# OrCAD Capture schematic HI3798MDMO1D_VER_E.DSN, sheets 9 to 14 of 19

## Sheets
9 SHEET09: size Custom
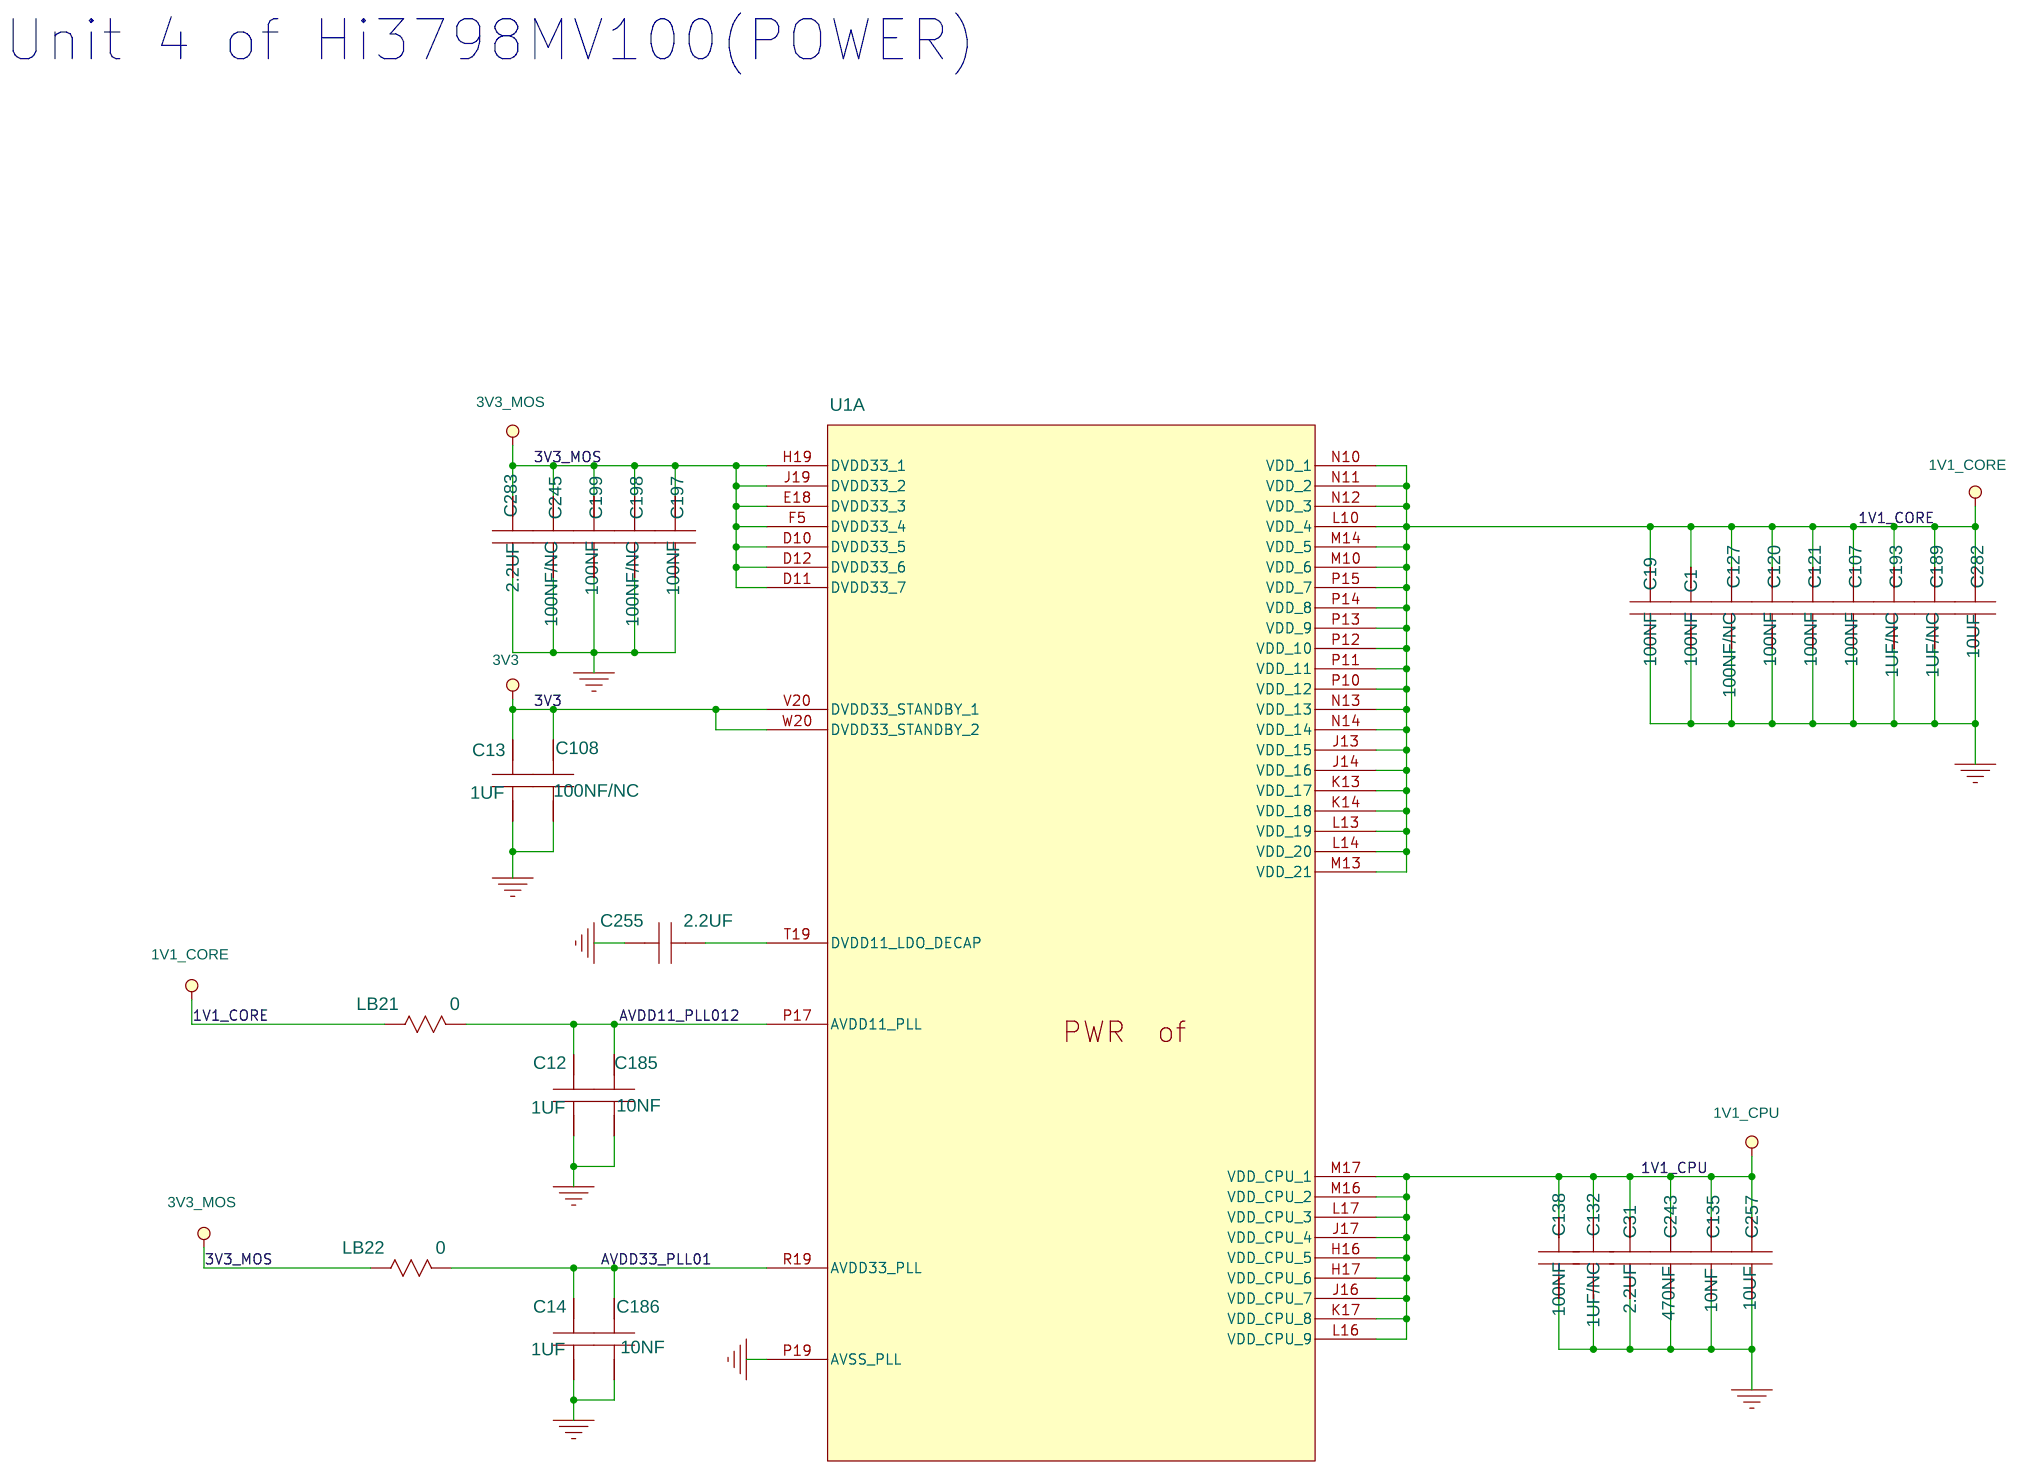
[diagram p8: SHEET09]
10 SHEET10: size Custom
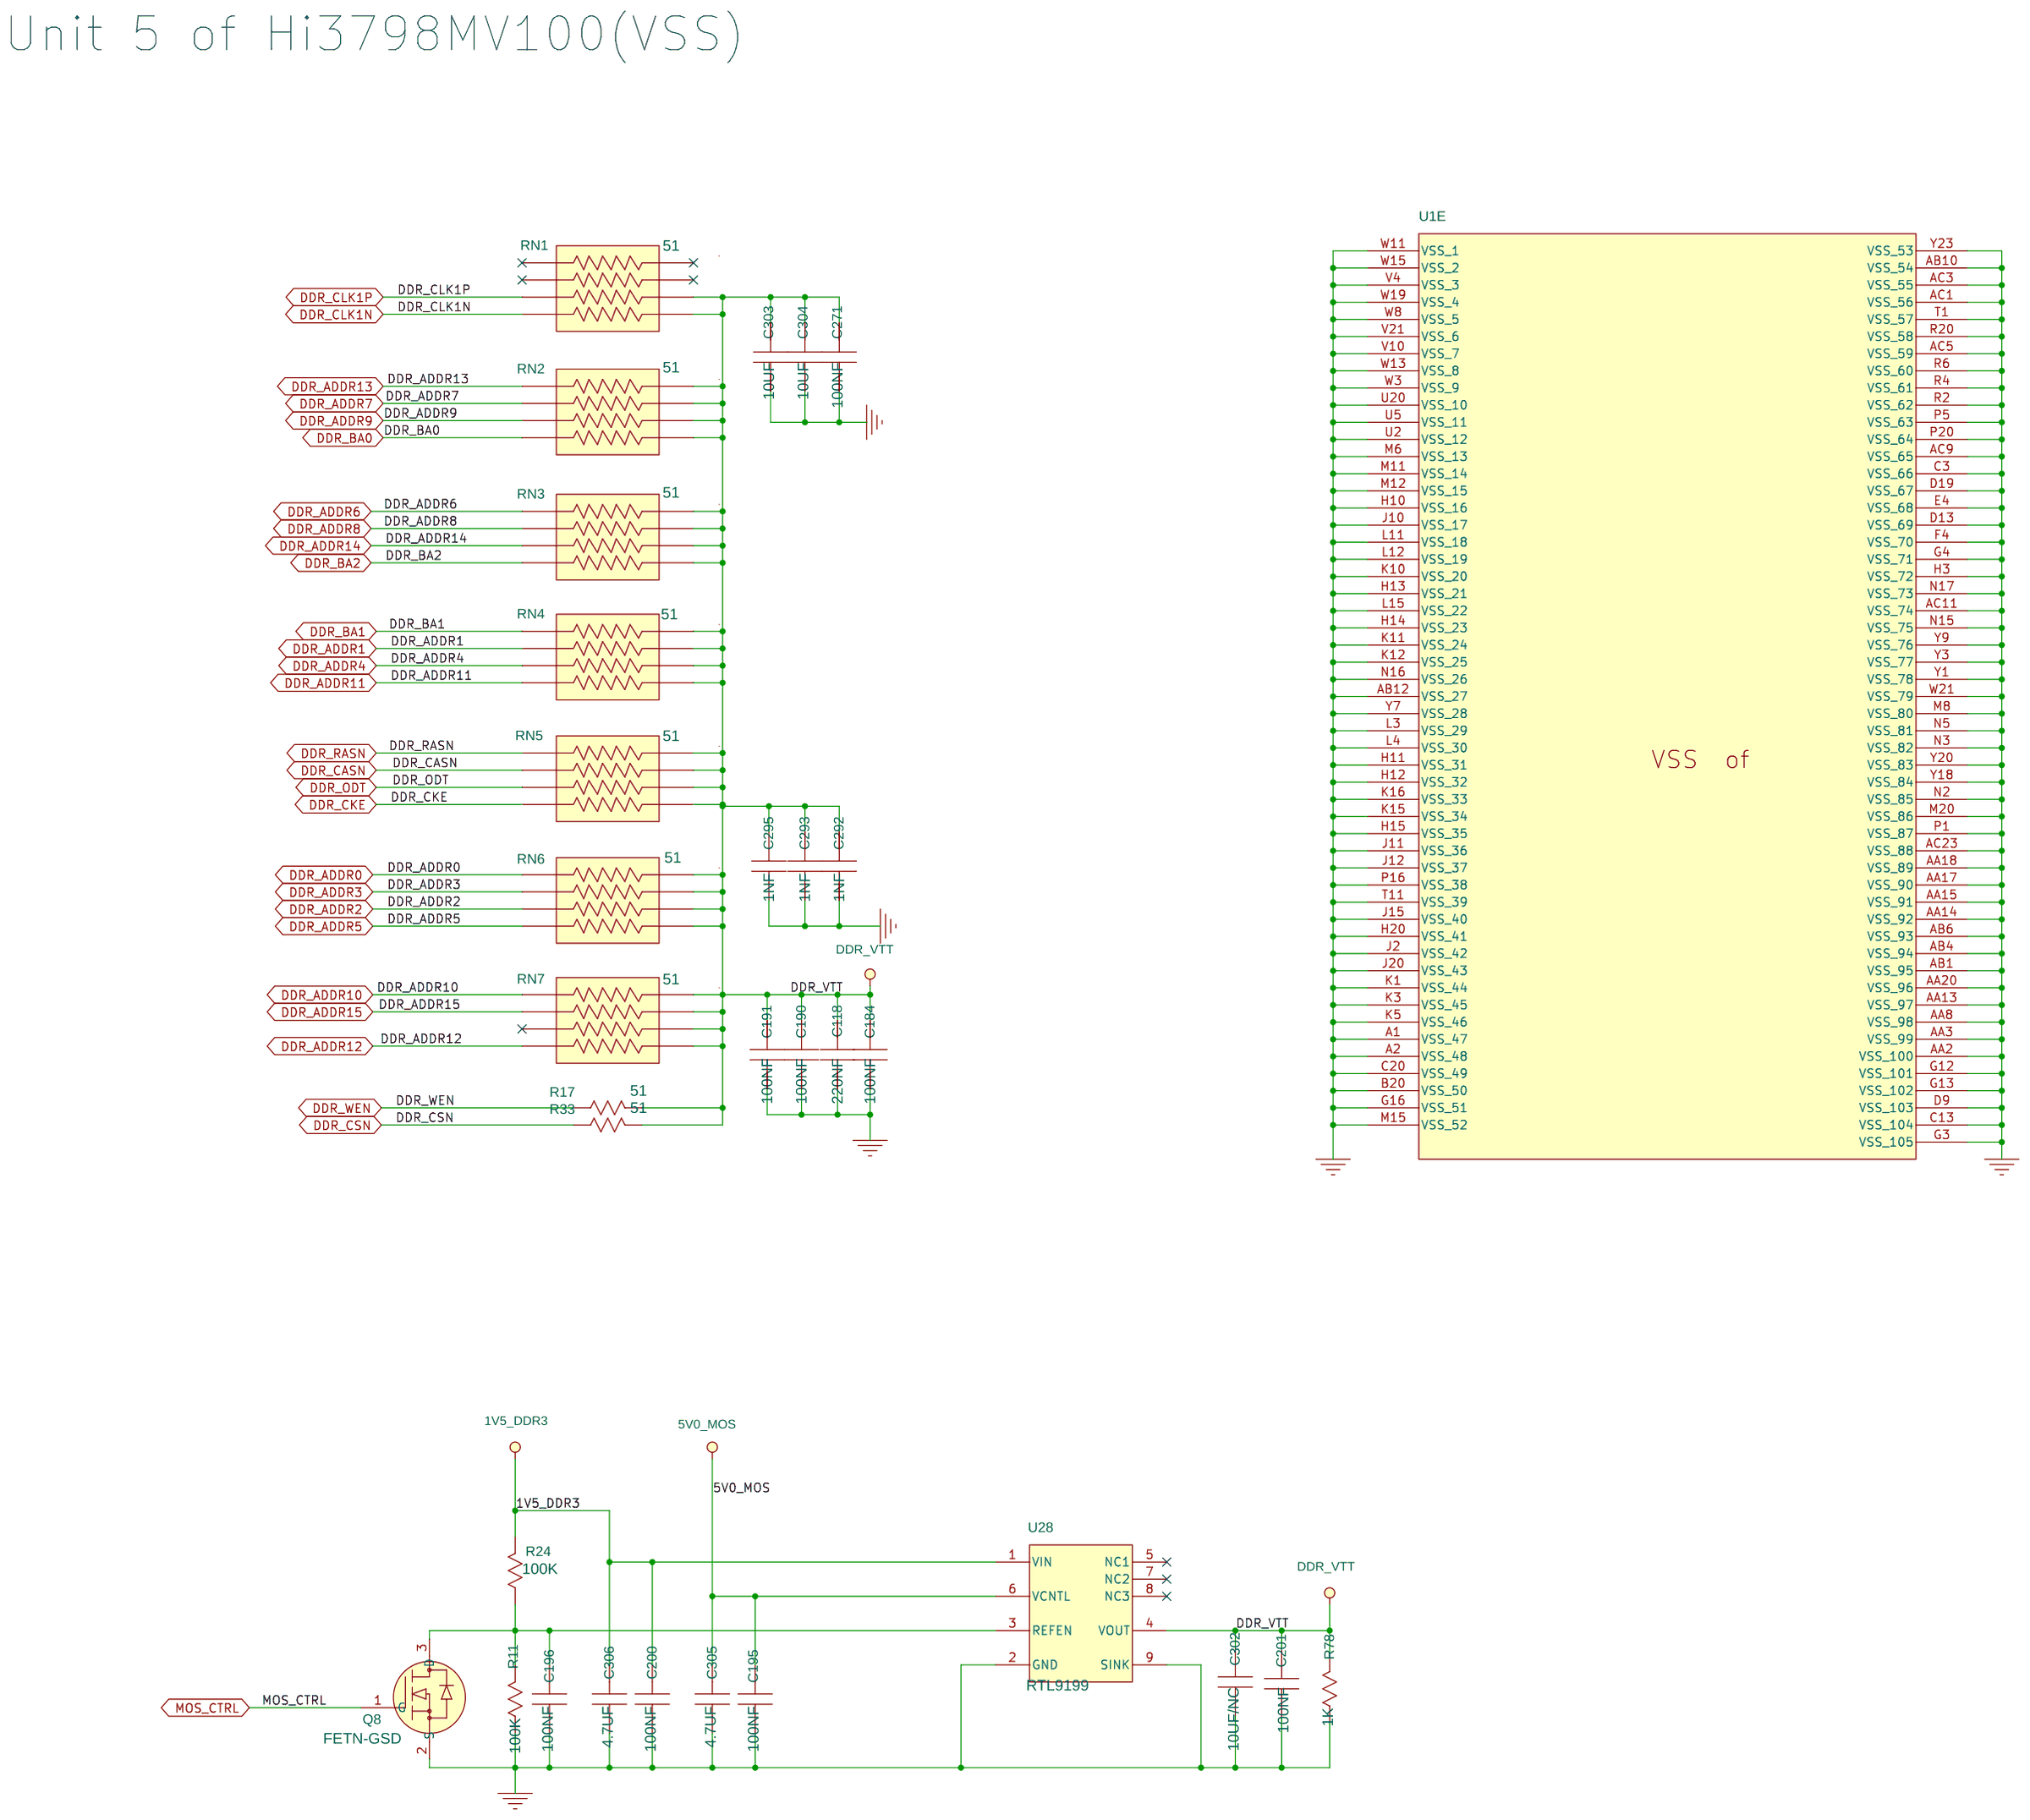
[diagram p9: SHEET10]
11 SHEET11: size Custom
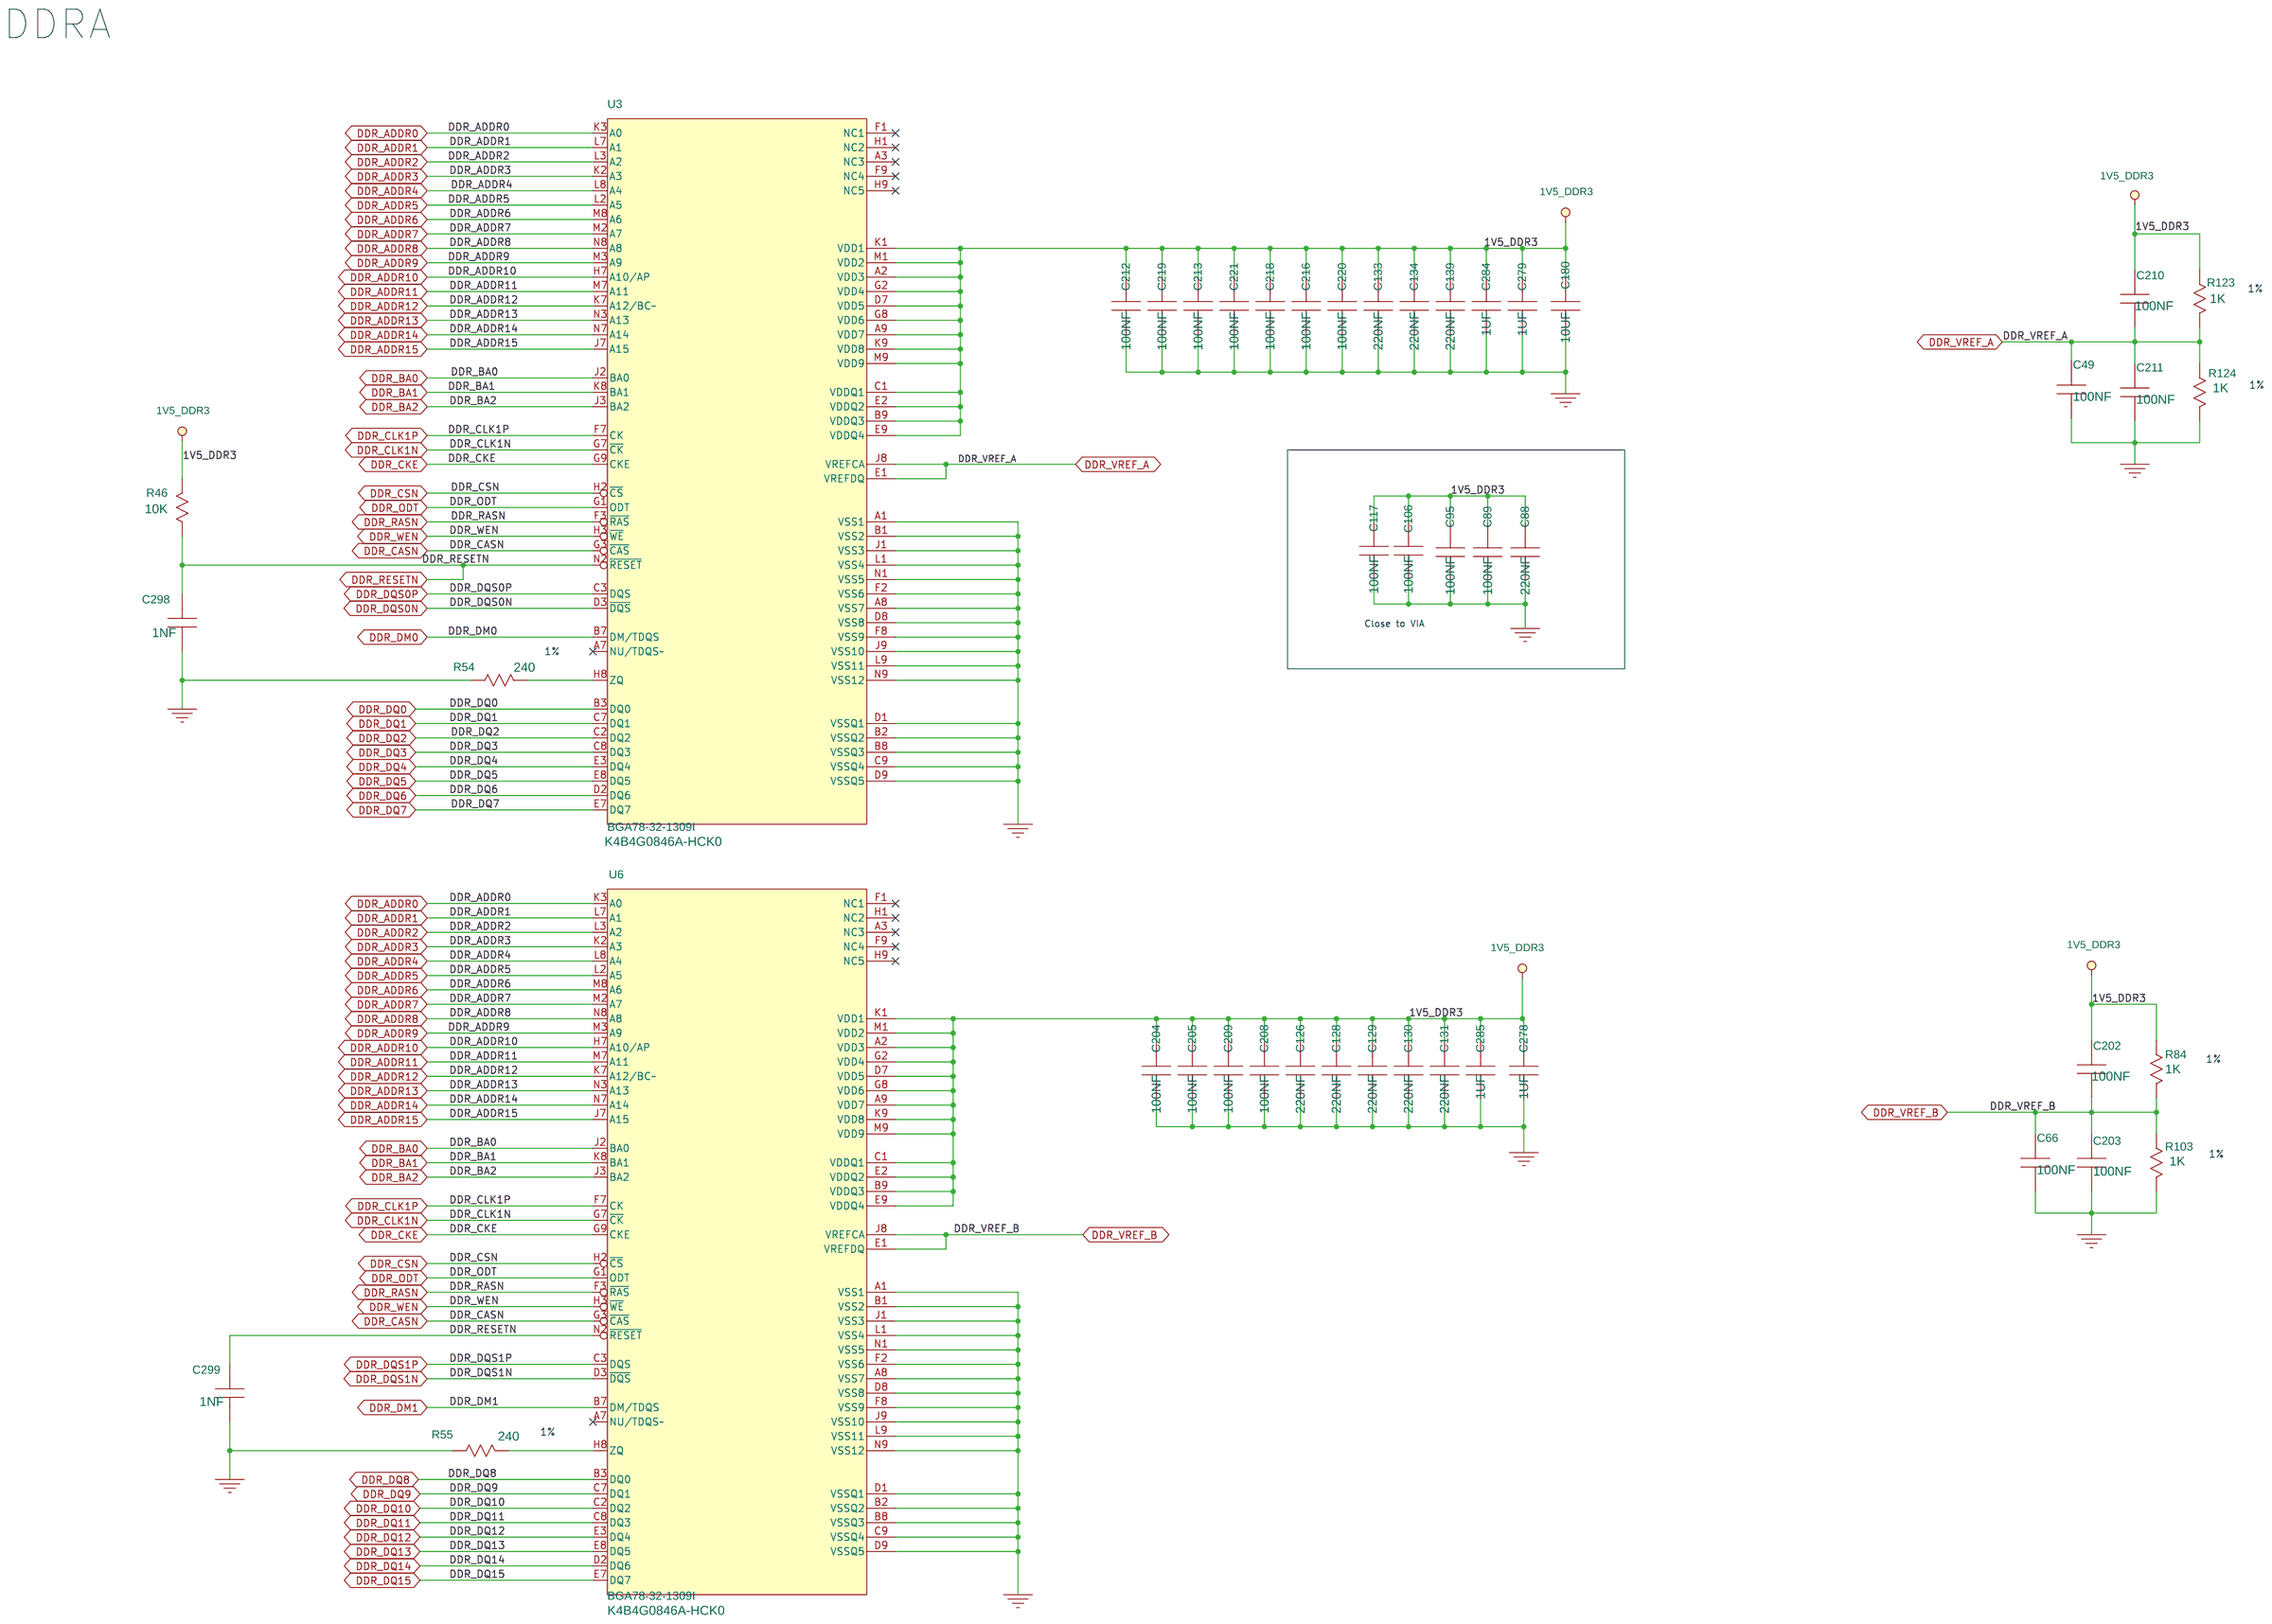
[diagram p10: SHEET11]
12 SHEET12: size Custom
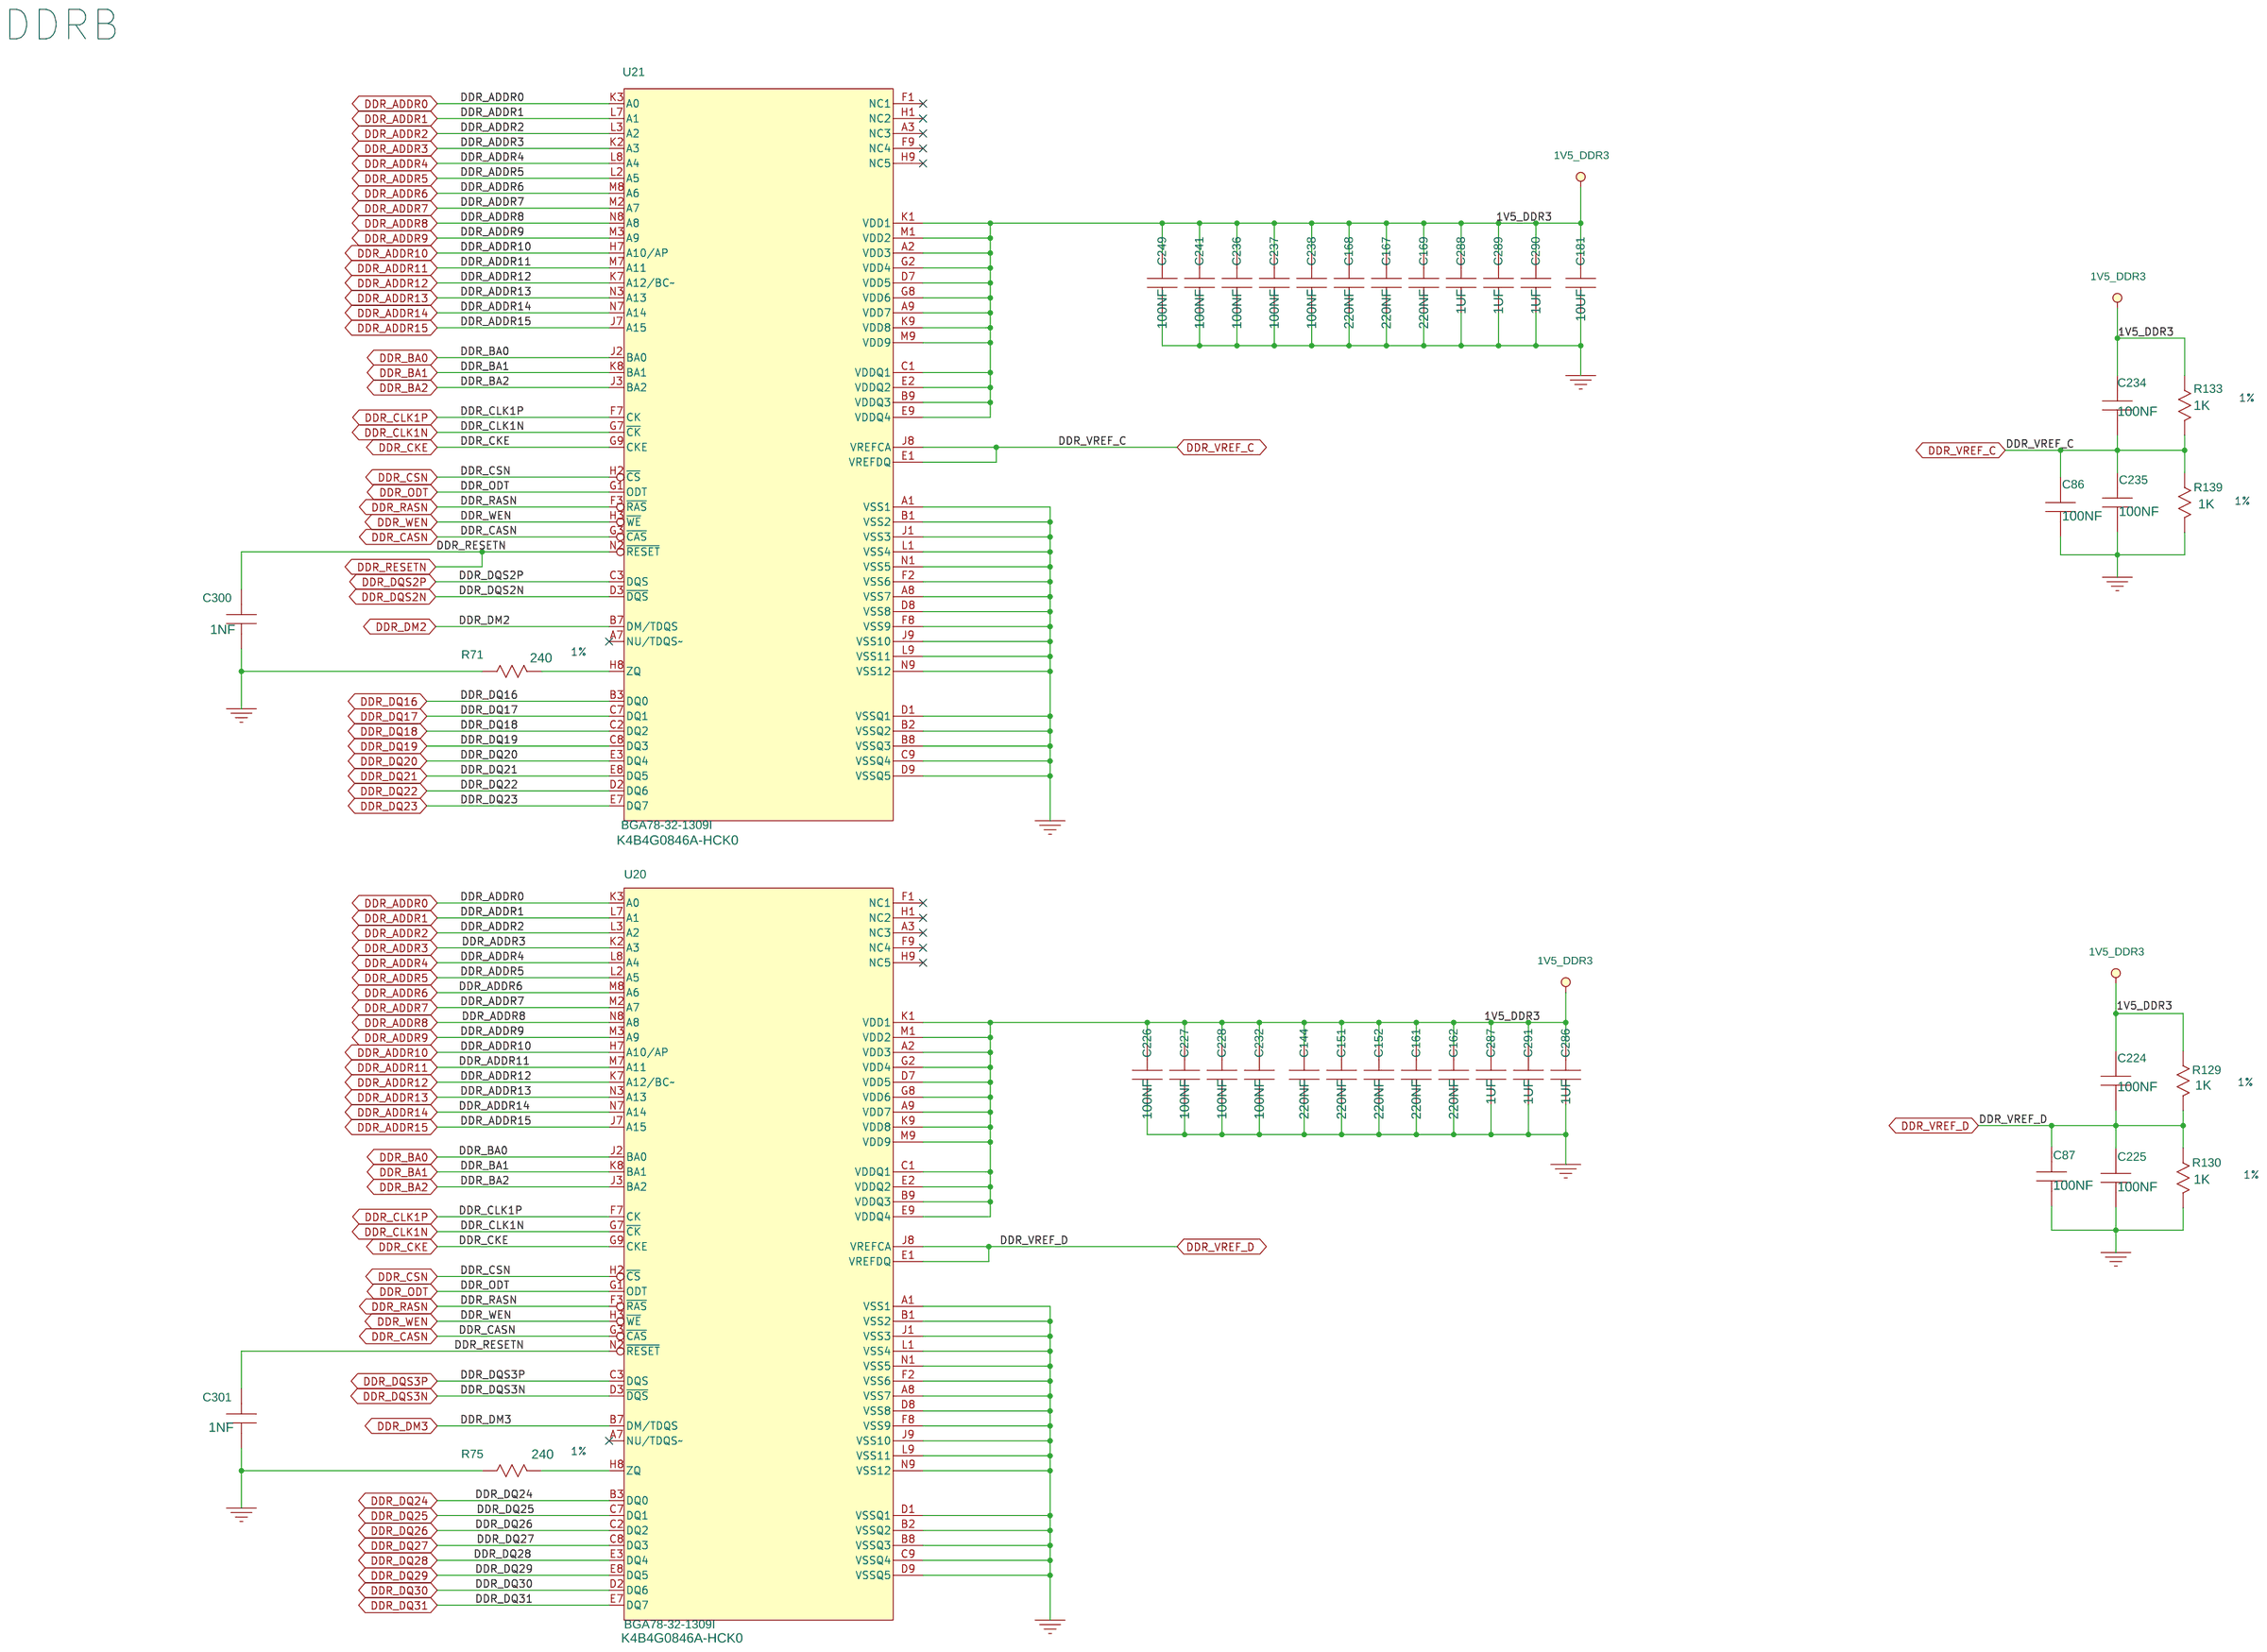
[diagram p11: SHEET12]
13 SHEET13: size Custom
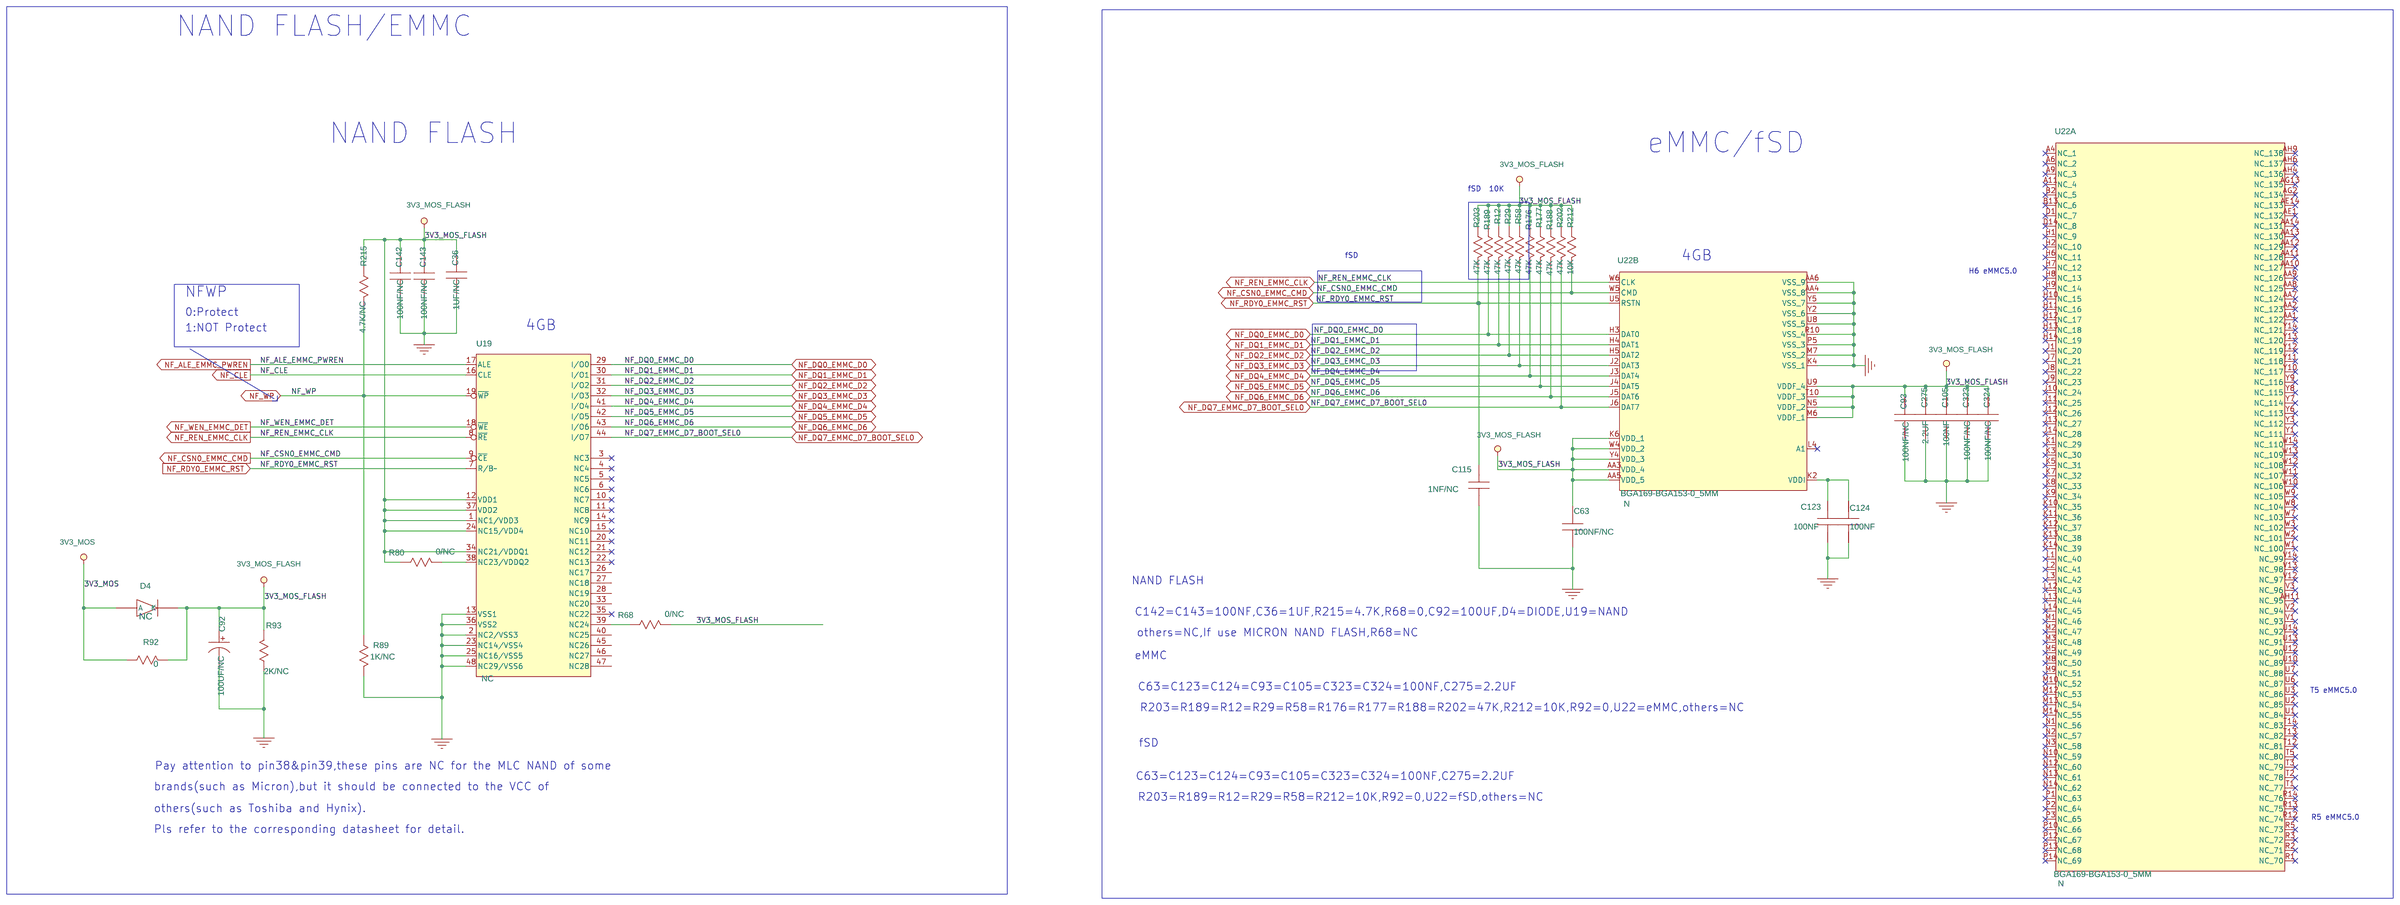
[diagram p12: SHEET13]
14 SHEET14: size Custom

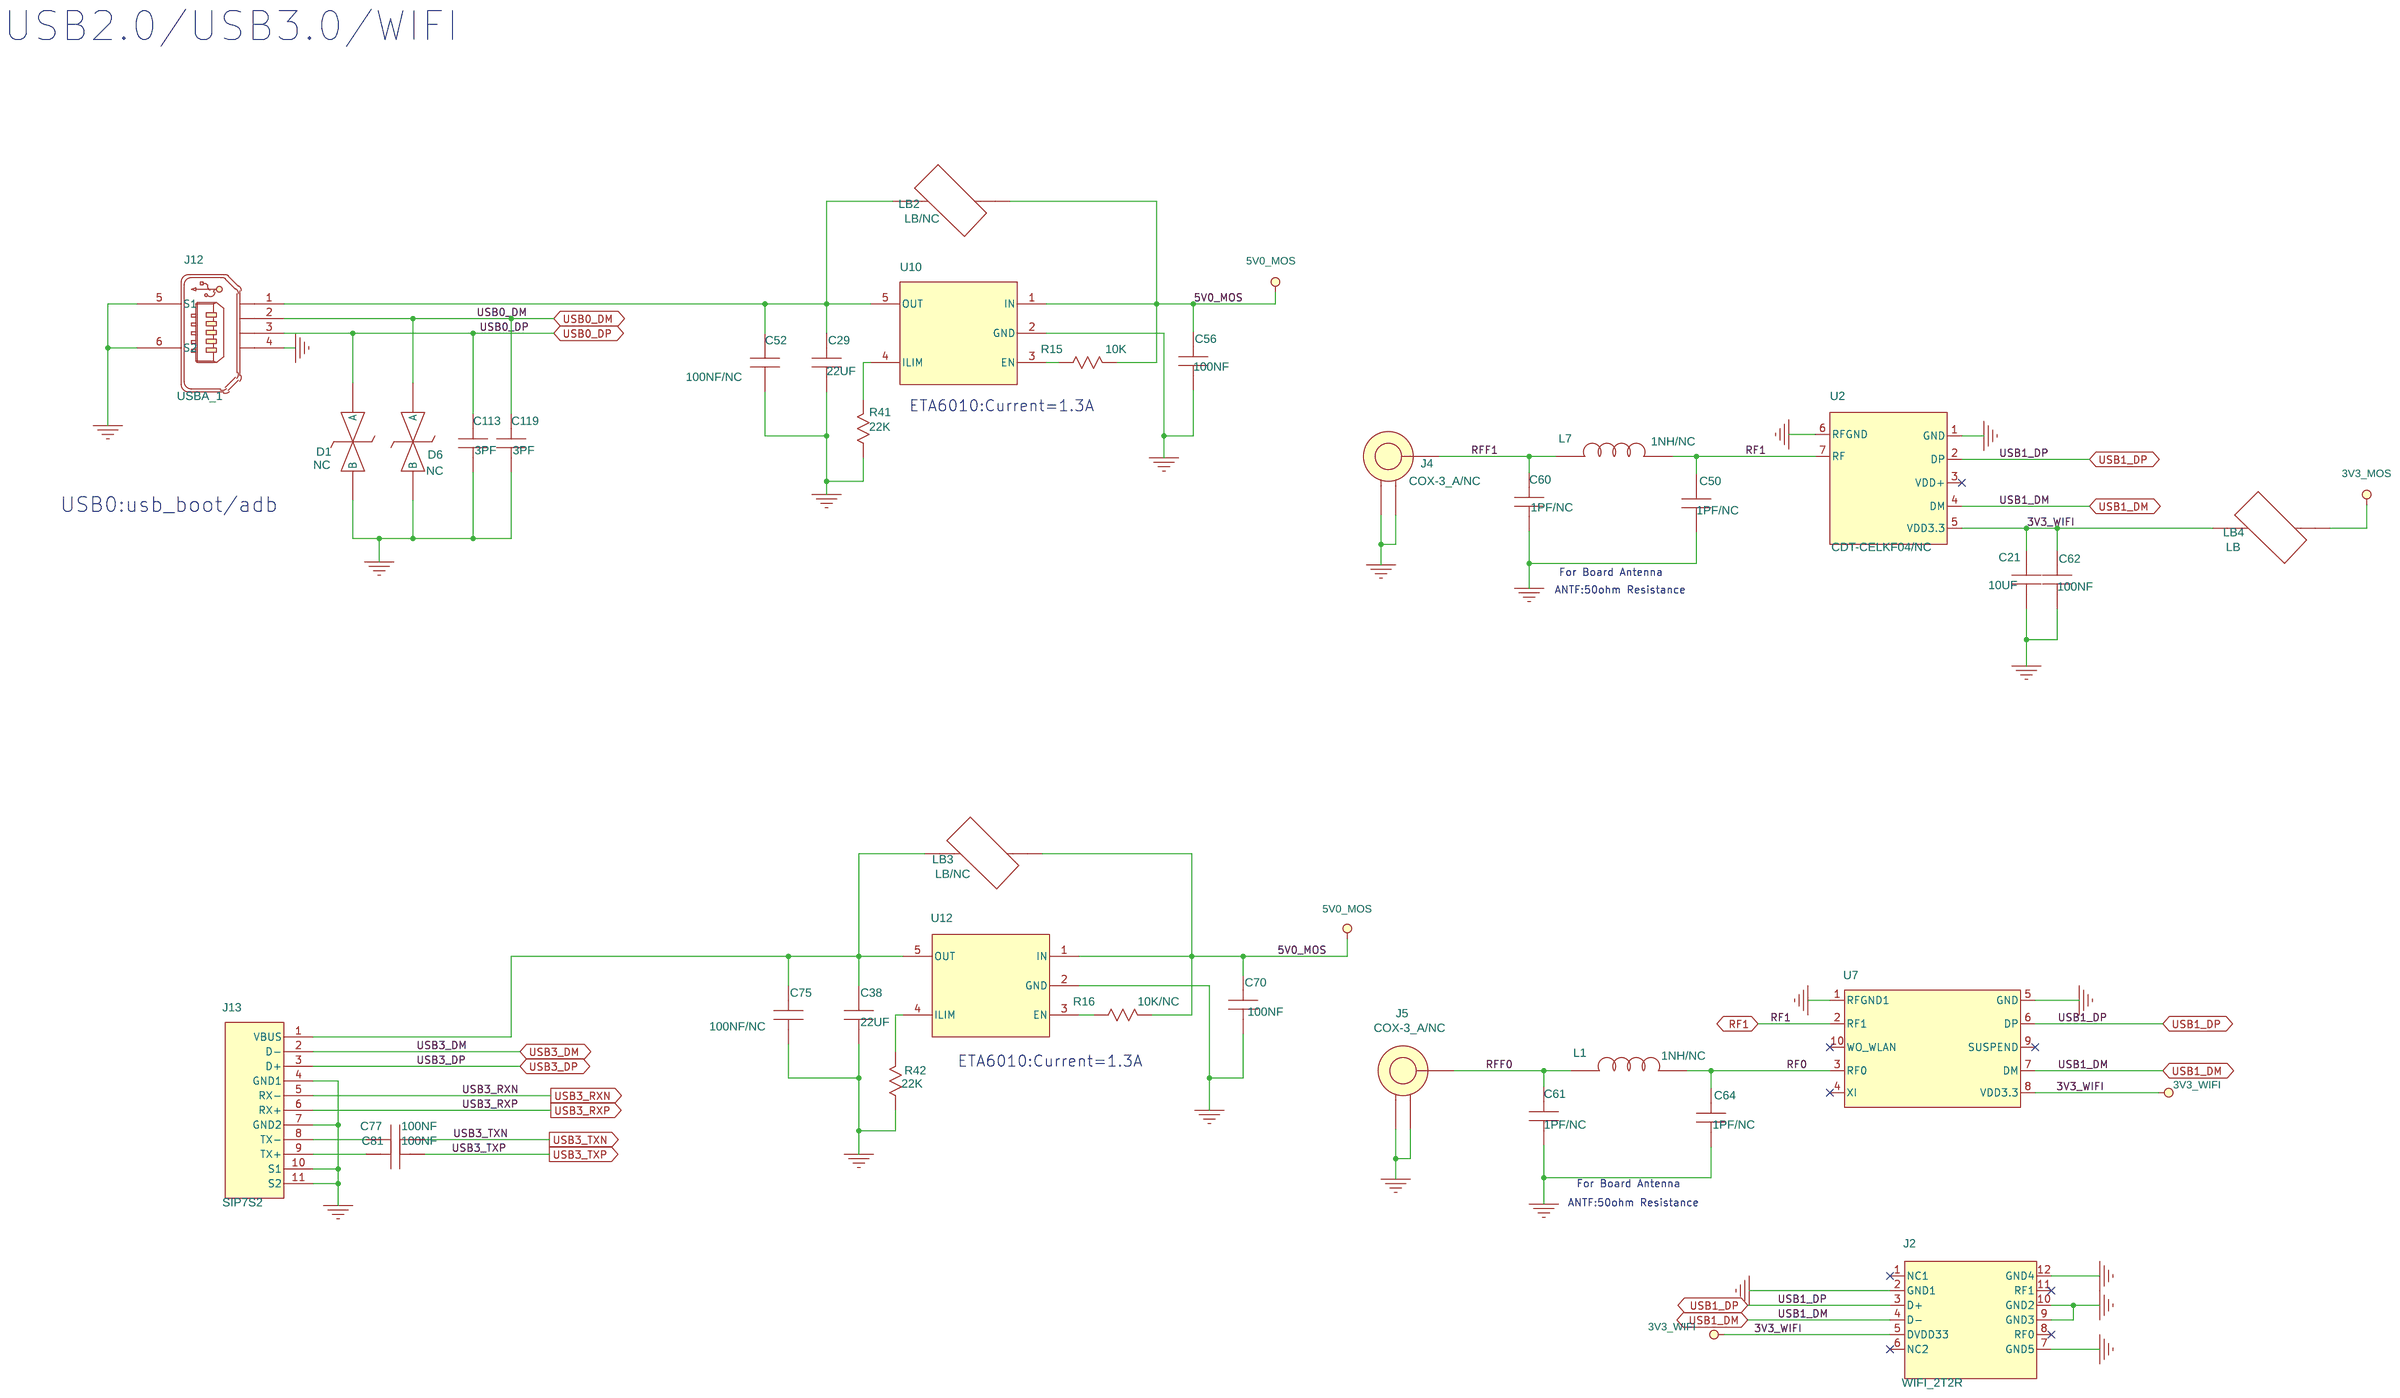
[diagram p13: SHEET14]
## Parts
sheet SHEET07
U1  Hi3798MV100_A  [TFBGA395-32-2323]  (sections A,B,C,D,E)
sheet SHEET09
C1  100NF  [SC0402]
C12  1UF  [SC0402]
C13  1UF  [SC0603]
C14  1UF  [SC0402]
C19  100NF  [SC0402]
C31  2.2UF  [HSC0402]
C107  100NF  [SC0402]
C108  100NF/NC  [SC0402]
C120  100NF  [SC0402]
C121  100NF  [SC0402]
C127  100NF/NC  [SC0402]
C132  1UF/NC  [SC0402]
C135  10NF  [HSC0402]
C138  100NF  [SC0402]
C185  10NF  [SC0402]
C186  10NF  [SC0402]
C189  1UF/NC  [SC0402]
C193  1UF/NC  [SC0402]
C197  100NF  [SC0402]
C198  100NF/NC  [SC0402]
C199  100NF  [SC0402]
C243  470NF  [SC0402]
C245  100NF/NC  [SC0402]
C255  2.2UF  [HSC0402]
C257  10UF  [SC0603]
C282  10UF  [SC0603]
C283  2.2UF  [SC0603]
LB21  0  [SL0603]
LB22  0  [SL0603]
sheet SHEET10
C118  220NF  [SC0402]
C184  100NF  [SC0402]
C190  100NF  [SC0402]
C191  100NF  [SC0402]
C195  100NF  [SC0402]
C196  100NF  [SC0402]
C200  100NF  [SC0402]
C201  100NF  [SC0402]
C271  100NF  [SC0402]
C292  1NF  [SC0402]
C293  1NF  [SC0402]
C295  1NF  [SC0402]
C302  10UF/NC  [SC0603]
C303  10UF  [SC0603]
C304  10UF  [SC0603]
C305  4.7UF  [SC0603]
C306  4.7UF  [SC0603]
Q8  FETN-GSD  [HSOT-SC70]
R11  100K  [SR0402]
R17  51  [SR0402]
R24  100K  [SR0402]
R33  51  [SR0402]
R78  1K  [SR0402]
RN1  51  [SRN8-0804]
RN2  51  [SRN8-0804]
RN3  51  [SRN8-0804]
RN4  51  [SRN8-0804]
RN5  51  [SRN8-0804]
RN6  51  [SRN8-0804]
RN7  51  [SRN8-0804]
U28  RTL9199  [SOP8H-50-200]
sheet SHEET11
C49  100NF  [SC0402]
C66  100NF  [SC0402]
C88  220NF  [SC0402]
C89  100NF  [SC0402]
C95  100NF  [SC0402]
C106  100NF  [SC0402]
C117  100NF  [SC0402]
C126  220NF  [SC0402]
C128  220NF  [SC0402]
C129  220NF  [SC0402]
C130  220NF  [SC0402]
C131  220NF  [SC0402]
C133  220NF  [SC0402]
C134  220NF  [SC0402]
C139  220NF  [SC0402]
C180  10UF  [SC0603]
C202  100NF  [SC0402]
C203  100NF  [SC0402]
C204  100NF  [SC0402]
C205  100NF  [SC0402]
C208  100NF  [SC0402]
C209  100NF  [SC0402]
C210  100NF  [SC0402]
C211  100NF  [SC0402]
C212  100NF  [SC0402]
C213  100NF  [SC0402]
C216  100NF  [SC0402]
C218  100NF  [SC0402]
C219  100NF  [SC0402]
C220  100NF  [SC0402]
C221  100NF  [SC0402]
C278  1UF  [SC0402]
C279  1UF  [SC0402]
C284  1UF  [SC0402]
C285  1UF  [SC0402]
C298  1NF  [SC0402]
C299  1NF  [SC0402]
R46  10K  [SR0402]
R54  240  [SR0402]
R55  240  [SR0402]
R84  1K  [SR0402]
R103  1K  [SR0402]
R123  1K  [SR0402]
R124  1K  [SR0402]
U3  K4B4G0846A-HCK0  [BGA78-32-1309I]
U6  K4B4G0846A-HCK0  [BGA78-32-1309I]
sheet SHEET12
C86  100NF  [SC0402]
C87  100NF  [SC0402]
C144  220NF  [SC0402]
C151  220NF  [SC0402]
C152  220NF  [SC0402]
C161  220NF  [SC0402]
C162  220NF  [SC0402]
C167  220NF  [SC0402]
C168  220NF  [SC0402]
C169  220NF  [SC0402]
C181  10UF  [SC0603]
C224  100NF  [SC0402]
C225  100NF  [SC0402]
C226  100NF  [SC0402]
C227  100NF  [SC0402]
C228  100NF  [SC0402]
C232  100NF  [SC0402]
C234  100NF  [SC0402]
C235  100NF  [SC0402]
C236  100NF  [SC0402]
C237  100NF  [SC0402]
C238  100NF  [SC0402]
C241  100NF  [SC0402]
C249  100NF  [SC0402]
C286  1UF  [SC0402]
C287  1UF  [SC0402]
C288  1UF  [SC0402]
C289  1UF  [SC0402]
C290  1UF  [SC0402]
C291  1UF  [SC0402]
C300  1NF  [SC0402]
C301  1NF  [SC0402]
R71  240  [SR0402]
R75  240  [SR0402]
R129  1K  [SR0402]
R130  1K  [SR0402]
R133  1K  [SR0402]
R139  1K  [SR0402]
U20  K4B4G0846A-HCK0  [BGA78-32-1309I]
U21  K4B4G0846A-HCK0  [BGA78-32-1309I]
sheet SHEET13
C36  1UF/NC  [SC0603]
C63  100NF/NC  [SC0402]
C92  100UF/NC  [SAC6666]
C93  100NF/NC  [SC0402]
C105  100NF  [SC0402]
C115  1NF/NC  [SC0402]
C123  100NF  [SC0402]
C124  100NF  [SC0402]
C142  100NF/NC  [SC0402]
C143  100NF/NC  [SC0402]
C275  2.2UF  [SC0603]
C323  100NF/NC  [SC0402]
C324  100NF/NC  [SC0402]
D4  NC  [HSOD323A]
R12  47K  [SR0402]
R29  47K  [SR0402]
R58  47K  [SR0402]
R68  0/NC  [SR0402]
R80  0/NC  [SR0402]
R89  1K/NC  [SR0402]
R92  0  [SR1206]
R93  2K/NC  [SR0603]
R176  47K  [SR0402]
R177  47K  [SR0402]
R188  47K  [SR0402]
R189  47K  [SR0402]
R202  47K  [SR0402]
R203  47K  [SR0402]
R212  10K  [SR0402]
R215  4.7K/NC  [SR0402]
U19  NC  [SOP48-20-720B]
U22  N  [BGA169-BGA153-0_5MM]  (sections A,B)
sheet SHEET14
C21  10UF  [SC0603]
C29  22UF  [SC0805]
C38  22UF  [SC0805]
C50  1PF/NC  [SC0402]
C52  100NF/NC  [SC0603]
C56  100NF  [SC0603]
C60  1PF/NC  [SC0402]
C61  1PF/NC  [SC0402]
C62  100NF  [SC0603]
C64  1PF/NC  [SC0402]
C70  100NF  [SC0603]
C75  100NF/NC  [SC0603]
C77  100NF  [SC0402]
C81  100NF  [SC0402]
C113  3PF  [SC0402]
C119  3PF  [SC0402]
D1  NC  [SC0402]
D6  NC  [SC0402]
J2  WIFI_2T2R  [SIP12-2_0MM-1827]
J4  COX-3_A/NC  [HSCOX-AMC-TM-A]
J5  COX-3_A/NC  [HSCOX-AMC-TM-A]
J12  USBA_1  [USB4-1415]
J13  SIP7S2  [USB3_0_9P_DIP_MAINSUPER]
L1  1NH/NC  [SL0402]
L7  1NH/NC  [SL0402]
LB2  LB/NC  [SL0603]
LB3  LB/NC  [SL0603]
LB4  LB  [SL0805]
R15  10K  [SR0402]
R16  10K/NC  [SR0402]
R41  22K  [SR0402]
R42  22K  [SR0402]
U2  CDT-CELKF04/NC  [CDTWIFI]
U7  NC  [CDTWIFI10]
U10  NC  [SOT23-5]
U12  NC  [SOT23-5]

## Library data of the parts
U1 = Hi3798MV100: CaptureCellPackProp: S40V300_19X19_VSSA
C1 C19 C49 C66 C77 C81 C86 C87 C89 C93 C95 C105-C108 C115 C117 C120 C121 C123 C124 C127 C138 C197-C199 C202-C205 C208-C213 C216 C218-C221 C224-C228 C232 C234-C238 C241 C245 C249 C323 C324 = C: %182%%238%%182%%168%%185%%164%%215%%247%%181%%231%%209%%185%(V): 10; %195%%232%%202%%246%: SMD陶瓷电容-10V-100NF-+/-10%-X5R-0402; %208%%161%%192%%224%%195%%251%%179%%198%: SMD陶瓷电容; CODE: 8070561; COMPONENT_HIGH_MAX: 0.55MM; DEVICE: C0402C104K8PAC_7867
C12 C14 C132 C189 C193 C278 C279 C284-C291 = C: %182%%238%%182%%168%%185%%164%%215%%247%%181%%231%%209%%185%(V): 10; %195%%232%%202%%246%: SMD陶瓷电容-10V-1000NF-+/-10%-X5R-0402-BT,TS16949; %208%%161%%192%%224%%195%%251%%179%%198%: SMD陶瓷电容; CODE: 8070612; COMPONENT_HIGH_MAX: 0.55MM; DEVICE: CV05X5R105K10AH
C13 C36 = C: %182%%238%%182%%168%%185%%164%%215%%247%%181%%231%%209%%185%(V): 25; %195%%232%%202%%246%: SMD陶瓷电容-25V-1000NF-+/-10%-X7R-0603; %208%%161%%192%%224%%195%%251%%179%%198%: SMD陶瓷电容; CODE: 8070962; COMPONENT_HIGH_MAX: 0.9MM; DEVICE: CETMK107B7105KA_T
C31 C255 = C: %182%%238%%182%%168%%185%%164%%215%%247%%181%%231%%209%%185%(V): 6.3; %195%%232%%202%%246%: SMD陶瓷电容-6.3V-2200NF-+/-20%-X5R-0402-TS16949; %208%%161%%192%%224%%195%%251%%179%%198%: SMD陶瓷电容; CODE: 8070667; COMPONENT_HIGH_MAX: 0.6MM; DEVICE: GRM155R60J225ME15D
C135 C185 C186 = C: %182%%238%%182%%168%%185%%164%%215%%247%%181%%231%%209%%185%(V): 16; %195%%232%%202%%246%: SMD陶瓷电容-16V-10NF-+/-10%-X7R-0402-BT,TS16949; %208%%161%%192%%224%%195%%251%%179%%198%: SMD陶瓷电容; CODE: 8070449; COMPONENT_HIGH_MAX: 0.55MM; DEVICE: GRM155R71C103KA01D
C243 = C: %182%%238%%182%%168%%185%%164%%215%%247%%181%%231%%209%%185%(V): 6.3; %195%%232%%202%%246%: SMD陶瓷电容-6.3V-470NF-+/-10%-X5R-0402; %208%%161%%192%%224%%195%%251%%179%%198%: SMD陶瓷电容; CODE: 8070625; COMPONENT_HIGH_MAX: 0.55MM; DEVICE: GRM155R60J474KE19D
C21 C257 C282 C302-C304 = C: %182%%238%%182%%168%%185%%164%%215%%247%%181%%231%%209%%185%(V): 6.3; %195%%232%%202%%246%: SMD陶瓷电容-6.3V-10000NF-+/-20%-X5R-0603-BT,TS16949; %208%%161%%192%%224%%195%%251%%179%%198%: SMD陶瓷电容; CODE: 8070649; COMPONENT_HIGH_MAX: 0.9MM; DEVICE: C1608X5R0J106MT0A0E
C283 = C: %182%%238%%182%%168%%185%%164%%215%%247%%181%%231%%209%%185%(V): 6.3; %195%%232%%202%%246%: SMD陶瓷电容-6.3V-2200NF-+/-10%-X5R-0603-BT; %208%%161%%192%%224%%195%%251%%179%%198%: SMD陶瓷电容; CODE: 8070563; COMPONENT_HIGH_MAX: 0.95MM; DEVICE: CM105X5R225K06AT
LB21 LB22 R68 R80 = R: %182%%238%%182%%168%%185%%166%%194%%202%(W): 0.06; %195%%232%%202%%246%: 片式厚膜电阻器-0.0625W-0OHM-< 50MOHM-0402-1A-BT; %208%%161%%192%%224%%195%%251%%179%%198%: 片式厚膜电阻器; %215%%232%%214%%181%%212%%202%%208%%237%%198%%171%%178%%238%: < 50MOHM; CODE: 7090800; COMPONENT_HIGH_MAX: 0.4MM; DEVICE: RC0402JR_070R
C88 C118 C126 C128-C131 C133 C134 C139 C144 C151 C152 C161 C162 C167-C169 = C: %182%%238%%182%%168%%185%%164%%215%%247%%181%%231%%209%%185%(V): 6.3; %195%%232%%202%%246%: SMD陶瓷电容-6.3V-220NF-+/-10%-X5R-0402-BT; %208%%161%%192%%224%%195%%251%%179%%198%: SMD陶瓷电容; CODE: 8070584; COMPONENT_HIGH_MAX: 0.55MM; DEVICE: GRM155R60J224KE01D
C184 C190 C191 C195 C196 C200 C201 C271 = C: %182%%238%%182%%168%%185%%164%%215%%247%%181%%231%%209%%185%(V): 16; %195%%232%%202%%246%: SMD陶瓷电容-16V-100NF-+/-10%-X7R-0402-BT; %208%%161%%192%%224%%195%%251%%179%%198%: SMD陶瓷电容; CODE: 8070614; COMPONENT_HIGH_MAX: 0.6MM; DEVICE: RMEMK105BJ104KV_FR
C63 C292 C293 C295 C298-C301 = C: %182%%238%%182%%168%%185%%164%%215%%247%%181%%231%%209%%185%(V): 50; %195%%232%%202%%246%: SMD陶瓷电容-50V-1NF-+/-10%-X7R-0402-BT; %208%%161%%192%%224%%195%%251%%179%%198%: SMD陶瓷电容; CODE: 8070531; COMPONENT_HIGH_MAX: 0.56MM; DEVICE: 04025C102KAT2A
C305 C306 = C: %182%%238%%182%%168%%185%%164%%215%%247%%181%%231%%209%%185%(V): 6.3; %195%%232%%202%%246%: SMD陶瓷电容-6.3V-4700NF-+/-20%-X5R-0603-BT,TS16949; %208%%161%%192%%224%%195%%251%%179%%198%: SMD陶瓷电容; CODE: 8070564; COMPONENT_HIGH_MAX: 0.95MM; DEVICE: CM105X5R475M06AT
Q8 = FETN-GSD: %195%%232%%202%%246%: MOSFET-N沟道-60V-0.3A-2000MOHM-20V-SOT323-供电专用; %208%%161%%192%%224%%195%%251%%179%%198%: MOSFET; CODE: 15060225; COMPONENT_HIGH_MAX: 1.1MM; DEVICE: 2N7002WT1G
R11 R24 = R: %182%%238%%182%%168%%185%%166%%194%%202%(W): 0.06; %195%%232%%202%%246%: 片式厚膜电阻器-0.0625W-100000OHM-+/-5%-0402-BT; %208%%161%%192%%224%%195%%251%%179%%198%: 片式厚膜电阻器; %215%%232%%214%%181%%212%%202%%208%%237%%198%%171%%178%%238%: +/-5%; CODE: 7090831; DEVICE: RK73B1ELTP104J
R17 R33 = R: %182%%238%%182%%168%%185%%166%%194%%202%(W): 0.06; %195%%232%%202%%246%: 片式厚膜电阻器-0.0625W-51OHM-+/-5%-0402; %208%%161%%192%%224%%195%%251%%179%%198%: 片式厚膜电阻器; %215%%232%%214%%181%%212%%202%%208%%237%%198%%171%%178%%238%: +/-5%; CODE: 7090610; COMPONENT_HIGH_MAX: 0.4MM; DEVICE: RC0402JR_0751R
R78 R84 R103 R123 R124 R129 R130 R133 R139 = R: %182%%238%%182%%168%%185%%166%%194%%202%(W): 0.06; %195%%232%%202%%246%: 片式厚膜电阻器-0.0625W-1000OHM-+/-1%-0402-BT; %208%%161%%192%%224%%195%%251%%179%%198%: 片式厚膜电阻器; %215%%232%%214%%181%%212%%202%%208%%237%%198%%171%%178%%238%: +/-1%; CODE: 7091282; COMPONENT_HIGH_MAX: 0.4MM; DEVICE: RC0402FR_071KL
RN1-RN7 = RND8-4: %195%%232%%202%%246%: 电阻网络-0.0625W-51OHM-4个-8PIN-+/-5%-SMT-小型-独立式-2.0*1.0*0.45-0.5MM; %208%%161%%192%%224%%195%%251%%179%%198%: 电阻网络; %215%%232%%214%%181%%212%%202%%208%%237%%198%%171%%178%%238%: +/-5%; CODE: 7080125; COMPONENT_HIGH_MAX: 0.5MM; DEVICE: CN1E4KTTD510J
U28 = RTL9199
C180 C181 = C: %182%%238%%182%%168%%185%%164%%215%%247%%181%%231%%209%%185%(V): 25; %195%%232%%202%%246%: SMD陶瓷电容-25V-10000NF-+80%-20%-Y5V-1206; %208%%161%%192%%224%%195%%251%%179%%198%: SMD陶瓷电容; CODE: 08070649; COMPONENT_HIGH_MAX: 0.9MM; DEVICE: C1608X5R0J106MT0A0E
R46 = R: %182%%238%%182%%168%%185%%166%%194%%202%(W): 0.06; %195%%232%%202%%246%: 片式厚膜电阻器-0.0625W-10000OHM-+/-1%-0402-BT; %208%%161%%192%%224%%195%%251%%179%%198%: 片式厚膜电阻器; %215%%232%%214%%181%%212%%202%%208%%237%%198%%171%%178%%238%: +/-1%; CODE: 7090867; COMPONENT_HIGH_MAX: 0.4MM; DEVICE: RK73H1ETTP1002F
R54 R55 R71 R75 = R: %182%%238%%182%%168%%185%%166%%194%%202%(W): 0.06; %195%%232%%202%%246%: 片式厚膜电阻器-0.0625W-240OHM-+/- 1%-0402-BT; %208%%161%%192%%224%%195%%251%%179%%198%: 片式厚膜电阻器; %215%%232%%214%%181%%212%%202%%208%%237%%198%%171%%178%%238%: +/- 1%; CODE: 7091782; COMPONENT_HIGH_MAX: 0.4MM; DEVICE: RC0402FR_07240RL
U3 U6 U20 U21 = K4B4G0846A-HCK0_0
C92 = CP: %182%%238%%182%%168%%185%%164%%215%%247%%181%%231%%209%%185%(V): 16; %195%%232%%202%%246%: 非固体SMD铝电容-16V-100UF-+/-20%-6.3*5.4MM-极性-105DEGC-1000H-片式,温度敏感器件-工艺耐温250DEGC,5S; %208%%161%%192%%224%%195%%251%%179%%198%: 非固体SMD铝电容; CODE: 8010269; COMPONENT_HIGH_MAX: 5.7MM; DEVICE: UWT1C101MCL1GB
C142 C143 = C: %182%%238%%182%%168%%185%%164%%215%%247%%181%%231%%209%%185%(V): 16; %195%%232%%202%%246%: SMD陶瓷电容-16V-100NF-±10%-X7R-0402; %208%%161%%192%%224%%195%%251%%179%%198%: SMD陶瓷电容; CODE: 8070614; COMPONENT_HIGH_MAX: 0.6MM; DEVICE: RMEMK105BJ104KV_FR
C275 = C: %182%%238%%182%%168%%185%%164%%215%%247%%181%%231%%209%%185%(V): 6.3; %195%%232%%202%%246%: SMD陶瓷电容-6.3V-2200NF-+/-10%-X5R-0603; %208%%161%%192%%224%%195%%251%%179%%198%: SMD陶瓷电容; CODE: 8070563; COMPONENT_HIGH_MAX: 0.95MM; DEVICE: CM105X5R225K06AT
D4 = D_A: %195%%232%%202%%246%: 肖特基二极管-10V-3A-0.24V-SOD323-BT; %208%%161%%192%%224%%195%%251%%179%%198%: 肖特基二极管; CODE: 15010252; COMPONENT_HIGH_MAX: 1.1MM; DEVICE: BAT60BE6327
R12 R29 R58 R176 R177 R188 R189 R202 R203 = R: %182%%238%%182%%168%%185%%166%%194%%202%(W): 0.06; %195%%232%%202%%246%: 片式厚膜电阻器-0.0625W-47000OHM-+/-5%-0402-ELOM; %208%%161%%192%%224%%195%%251%%179%%198%: 片式厚膜电阻器; %215%%232%%214%%181%%212%%202%%208%%237%%198%%171%%178%%238%: +/-5%; CODE: 7090819; DEVICE: RC0402JR_0747K
R89 = R: %182%%238%%182%%168%%185%%166%%194%%202%(W): 0.06; %195%%232%%202%%246%: 片式厚膜电阻器-0.0625W-1000OHM-±5%-0402; %208%%161%%192%%224%%195%%251%%179%%198%: 片式厚膜电阻器; %215%%232%%214%%181%%212%%202%%208%%237%%198%%171%%178%%238%: ±5%; CODE: 7090809; COMPONENT_HIGH_MAX: 0.4MM; DEVICE: RC0402JR_071KL
R92 R93 = R: %182%%238%%182%%168%%185%%166%%194%%202%(W): 0.1; %195%%232%%202%%246%: 片式厚膜电阻器-0.1W-4700OHM-+/-5%-0603-抗硫化; %208%%161%%192%%224%%195%%251%%179%%198%: 片式厚膜电阻器; %215%%232%%214%%181%%212%%202%%208%%237%%198%%171%%178%%238%: +/-5%; CODE: 7090246; DEVICE: RC0603JR_074K7
R15 R16 R212 = R: %182%%238%%182%%168%%185%%166%%194%%202%(W): 0.06; %195%%232%%202%%246%: 片式厚膜电阻器-0.0625W-10000OHM-+/-5%-0402-BT; %208%%161%%192%%224%%195%%251%%179%%198%: 片式厚膜电阻器; %215%%232%%214%%181%%212%%202%%208%%237%%198%%171%%178%%238%: +/-5%; CODE: 7090815; DEVICE: RC_02W103JT
R215 = R: %182%%238%%182%%168%%185%%166%%194%%202%(W): 0.06; %195%%232%%202%%246%: 片式厚膜电阻器-0.0625W-4700OHM-+/-5%-0402; %208%%161%%192%%224%%195%%251%%179%%198%: 片式厚膜电阻器; %215%%232%%214%%181%%212%%202%%208%%237%%198%%171%%178%%238%: +/-5%; CODE: 7090793; COMPONENT_HIGH_MAX: 0.4MM; DEVICE: RK73B1ELTP472J
U19 = MLC_NAND_0: CODE: *
U22 = N_0: CaptureCellPackProp: NA
C29 C38 = C: %182%%238%%182%%168%%185%%164%%215%%247%%181%%231%%209%%185%(V): 6.3; %195%%232%%202%%246%: SMD陶瓷电容-6.3V-22000NF-+/-20%-X5R-0805-08070784编码拆分供华为技术使用; %208%%161%%192%%224%%195%%251%%179%%198%: SMD陶瓷电容; CODE: 8071114; COMPONENT_HIGH_MAX: 1.35MM; DEVICE: C2012X5R0J226MT000N
C50 C60 C61 C64 = C: %182%%238%%182%%168%%185%%164%%215%%247%%181%%231%%209%%185%(V): 50; %195%%232%%202%%246%: SMD陶瓷电容-50V-0.001NF-+/-0.1PF-NPO-0402-BT; %208%%161%%192%%224%%195%%251%%179%%198%: SMD陶瓷电容; CODE: 8070578; COMPONENT_HIGH_MAX: 0.55MM; DEVICE: GRM1555C1H1R0B
C52 C56 C62 C70 C75 C113 C119 = C: %182%%238%%182%%168%%185%%164%%215%%247%%181%%231%%209%%185%(V): 50; %195%%232%%202%%246%: SMD陶瓷电容-50V-100NF-±10%-X7R-0603; %208%%161%%192%%224%%195%%251%%179%%198%: SMD陶瓷电容; CODE: 8070627; COMPONENT_HIGH_MAX: 0.9MM; DEVICE: C1608X7R1H104KT000N
D1 D6 = ULCE0505A015FR
J2 = WIFI_0
J4 J5 = COX-3_A: %195%%232%%202%%246%: 射频连接器-同轴连接器-50OHM-直式-MALE-SMT-终端专用-终端专用; %208%%161%%192%%224%%195%%251%%179%%198%: 射频连接器; CODE: 14240060; COMPONENT_HIGH_MAX: 1.45MM; DEVICE: 51_3612_50_H
J12 = USBA_1: CODE: 14080105
J13 = SIP7S2_0
L1 L7 = L: %195%%232%%202%%246%: 贴片电感器-0.001UH-5％-0.045OHM-1.36A-15DEGC-0402; %208%%161%%192%%224%%195%%251%%179%%198%: 贴片电感器; CODE: 10031232; COMPONENT_HIGH_MAX: 0.66MM; DEVICE: 0402CS_1N0XJLW
LB2 LB3 = LB_v2: %195%%232%%202%%246%: EMI磁珠-30OHM-0.05OHM-0.4A-0603-; %208%%161%%192%%224%%195%%251%%179%%198%: EMI磁珠; CODE: 10070003; COMPONENT_HIGH_MAX: 0.95MM; DEVICE: MGLB1608_030T_LF
LB4 = LB_v2: %195%%232%%202%%246%: EMI磁珠-+/-25%-220OHM-0.05OHM-2A-0805; %208%%161%%192%%224%%195%%251%%179%%198%: EMI磁珠; CODE: 10070012; COMPONENT_HIGH_MAX: 1.05MM; DEVICE: MGLB2012_220T_LF
R41 R42 = R: %182%%238%%182%%168%%185%%166%%194%%202%(W): 0.06; %195%%232%%202%%246%: 片式厚膜电阻器-0.0625W-22000OHM-+/-1%-0402; %208%%161%%192%%224%%195%%251%%179%%198%: 片式厚膜电阻器; %215%%232%%214%%181%%212%%202%%208%%237%%198%%171%%178%%238%: +/-1%; CODE: 7090798; COMPONENT_HIGH_MAX: 0.4MM; DEVICE: RK73H1ELTP2202F
U2 = CDT-CELKF04_0
U7 = CDT-CELKF10_0
U10 U12 = ETA6010: DEVICE: ETA6010_SGM2551A

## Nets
1V1_CORE: C1.1(A) C19.1(A) C107.1(A) C120.1(A) C121.1(A) C127.1(A) C189.1(A) C193.1(A) C282.1(A) LB21.1(A) U1.J13(VDD_15) U1.J14(VDD_16) U1.K13(VDD_17) U1.K14(VDD_18) U1.L10(VDD_4) U1.L13(VDD_19) U1.L14(VDD_20) U1.M10(VDD_6) U1.M13(VDD_21) U1.M14(VDD_5) U1.N10(VDD_1) U1.N11(VDD_2) U1.N12(VDD_3) U1.N13(VDD_13) U1.N14(VDD_14) U1.P10(VDD_12) U1.P11(VDD_11) U1.P12(VDD_10) U1.P13(VDD_9) U1.P14(VDD_8) U1.P15(VDD_7) ; also on sheet 4 6 7
1V1_CPU: C31.1(A) C132.1(A) C135.1(A) C138.1(A) C243.1(A) C257.1(A) U1.H16(VDD_CPU_5) U1.H17(VDD_CPU_6) U1.J16(VDD_CPU_7) U1.J17(VDD_CPU_4) U1.K17(VDD_CPU_8) U1.L16(VDD_CPU_9) U1.L17(VDD_CPU_3) U1.M16(VDD_CPU_2) U1.M17(VDD_CPU_1) ; also on sheet 4
1V5_DDR3: C88.1(A) C89.1(A) C95.1(A) C106.1(A) C117.1(A) C126.1(A) C128.1(A) C129.1(A) C130.1(A) C131.1(A) C133.1(A) C134.1(A) C139.1(A) C144.1(A) C151.1(A) C152.1(A) C161.1(A) C162.1(A) C167.1(A) C168.1(A) C169.1(A) C180.1(A) C181.1(A) C200.1(A) C202.1(A) C204.1(A) C205.1(A) C208.1(A) C209.1(A) C210.1(A) C212.1(A) C213.1(A) C216.1(A) C218.1(A) C219.1(A) C220.1(A) C221.1(A) C224.1(A) C226.1(A) C227.1(A) C228.1(A) C232.1(A) C234.1(A) C236.1(A) C237.1(A) C238.1(A) C241.1(A) C249.1(A) C278.1(A) C279.1(A) C284.1(A) C285.1(A) C286.1(A) C287.1(A) C288.1(A) C289.1(A) C290.1(A) C291.1(A) C306.1(A) R24.2(B) R46.2(B) R84.1(A) R123.1(A) R129.1(A) R133.1(A) U3.A2(VDD3) U3.A9(VDD7) U3.B9(VDDQ3) U3.C1(VDDQ1) U3.D7(VDD5) U3.E2(VDDQ2) U3.E9(VDDQ4) U3.G2(VDD4) U3.G8(VDD6) U3.K1(VDD1) U3.K9(VDD8) U3.M1(VDD2) U3.M9(VDD9) U6.A2(VDD3) U6.A9(VDD7) U6.B9(VDDQ3) U6.C1(VDDQ1) U6.D7(VDD5) U6.E2(VDDQ2) U6.E9(VDDQ4) U6.G2(VDD4) U6.G8(VDD6) U6.K1(VDD1) U6.K9(VDD8) U6.M1(VDD2) U6.M9(VDD9) U20.A2(VDD3) U20.A9(VDD7) U20.B9(VDDQ3) U20.C1(VDDQ1) U20.D7(VDD5) U20.E2(VDDQ2) U20.E9(VDDQ4) U20.G2(VDD4) U20.G8(VDD6) U20.K1(VDD1) U20.K9(VDD8) U20.M1(VDD2) U20.M9(VDD9) U21.A2(VDD3) U21.A9(VDD7) U21.B9(VDDQ3) U21.C1(VDDQ1) U21.D7(VDD5) U21.E2(VDDQ2) U21.E9(VDDQ4) U21.G2(VDD4) U21.G8(VDD6) U21.K1(VDD1) U21.K9(VDD8) U21.M1(VDD2) U21.M9(VDD9) U28.1(VIN) ; also on sheet 4 8
3V3: C13.1(A) C108.1(A) U1.V20(DVDD33_STANDBY_1) U1.W20(DVDD33_STANDBY_2) ; also on sheet 4 5 6 15 17
3V3_MOS: C197.1(A) C198.1(A) C199.1(A) C245.1(A) C283.1(A) D4.2(A) LB4.2 LB22.1(A) R92.1(A) U1.D10(DVDD33_5) U1.D11(DVDD33_7) U1.D12(DVDD33_6) U1.E18(DVDD33_3) U1.F5(DVDD33_4) U1.H19(DVDD33_1) U1.J19(DVDD33_2) ; also on sheet 5 6 7 8 15 17 18 19
3V3_MOS_FLASH: C36.1(A) C63.1(A) C92.1 C93.1(A) C105.1(A) C142.1(A) C143.1(A) C275.1(A) C323.1(A) C324.1(A) D4.1(K) R12.1(A) R29.1(A) R58.1(A) R68.2(B) R80.1(A) R92.2(B) R93.1(A) R176.1(A) R177.1(A) R188.1(A) R189.1(A) R202.1(A) R203.1(A) R212.1(A) R215.1(A) U19.1(NC1/VDD3) U19.12(VDD1) U19.24(NC15/VDD4) U19.34(NC21/VDDQ1) U19.37(VDD2) U22.AA3(VDD_4) U22.AA5(VDD_5) U22.K6(VDD_1) U22.M6(VDDF_1) U22.N5(VDDF_2) U22.T10(VDDF_3) U22.U9(VDDF_4) U22.W4(VDD_2) U22.Y4(VDD_3)
3V3_WIFI: C21.1(A) C62.1(A) J2.5(DVDD33) LB4.1 U2.5(VDD3.3) U7.8(VDD3.3)
5V0_MOS: C56.1(A) C70.1(A) C195.1(A) C305.1(A) LB2.2 LB3.2 R15.2(B) R16.2(B) U10.1(IN) U12.1(IN) U28.6(VCNTL) ; also on sheet 5 16 19
AVDD11_PLL012: C12.1(A) C185.1(A) LB21.2(B) U1.P17(AVDD11_PLL)
AVDD33_PLL01: C14.1(A) C186.1(A) LB22.2(B) U1.R19(AVDD33_PLL)
GND: C1.2(B) C12.2(B) C13.2(B) C14.2(B) C19.2(B) C21.2(B) C29.2(B) C31.2(B) C36.2(B) C38.2(B) C49.2(B) C50.2(B) C52.2(B) C56.2(B) C60.2(B) C61.2(B) C62.2(B) C63.2(B) C64.2(B) C66.2(B) C70.2(B) C75.2(B) C86.2(B) C87.2(B) C88.2(B) C89.2(B) C92.2 C93.2(B) C95.2(B) C105.2(B) C106.2(B) C107.2(B) C108.2(B) C113.2(B) C115.2(B) C117.2(B) C118.2(B) C119.2(B) C120.2(B) C121.2(B) C123.2(B) C124.2(B) C126.2(B) C127.2(B) C128.2(B) C129.2(B) C130.2(B) C131.2(B) C132.2(B) C133.2(B) C134.2(B) C135.2(B) C138.2(B) C139.2(B) C142.2(B) C143.2(B) C144.2(B) C151.2(B) C152.2(B) C161.2(B) C162.2(B) C167.2(B) C168.2(B) C169.2(B) C180.2(B) C181.2(B) C184.2(B) C185.2(B) C186.2(B) C189.2(B) C190.2(B) C191.2(B) C193.2(B) C195.2(B) C196.2(B) C197.2(B) C198.2(B) C199.2(B) C200.2(B) C201.2(B) C203.2(B) C204.2(B) C205.2(B) C208.2(B) C209.2(B) C211.2(B) C212.2(B) C213.2(B) C216.2(B) C218.2(B) C219.2(B) C220.2(B) C221.2(B) C225.2(B) C226.2(B) C227.2(B) C228.2(B) C232.2(B) C235.2(B) C236.2(B) C237.2(B) C238.2(B) C241.2(B) C243.2(B) C245.2(B) C249.2(B) C255.1(A) C257.2(B) C271.2(B) C275.2(B) C278.2(B) C279.2(B) C282.2(B) C283.2(B) C284.2(B) C285.2(B) C286.2(B) C287.2(B) C288.2(B) C289.2(B) C290.2(B) C291.2(B) C292.2(B) C293.2(B) C295.2(B) C298.2(B) C299.2(B) C300.2(B) C301.2(B) C302.2(B) C303.2(B) C304.2(B) C305.2(B) C306.2(B) C323.2(B) C324.2(B) D1.2(B) D6.2(B) J2.2(GND1) J2.7(GND5) J2.9(GND3) J2.10(GND2) J2.12(GND4) J4.2 J4.3 J5.2 J5.3 J12.4 J12.5(S1) J12.6(S2) J13.4(GND1) J13.7(GND2) J13.10(S1) J13.11(S2) Q8.2(S) R11.1(A) R41.1(A) R42.1(A) R54.1(A) R55.1(A) R71.1(A) R75.1(A) R78.1(A) R89.2(B) R93.2(B) R103.2(B) R124.2(B) R130.2(B) R139.2(B) U1.A1(VSS_47) U1.A2(VSS_48) U1.AA2(VSS_100) U1.AA3(VSS_99) U1.AA8(VSS_98) U1.AA13(VSS_97) U1.AA14(VSS_92) U1.AA15(VSS_91) U1.AA17(VSS_90) U1.AA18(VSS_89) U1.AA20(VSS_96) U1.AB1(VSS_95) U1.AB4(VSS_94) U1.AB6(VSS_93) U1.AB10(VSS_54) U1.AB12(VSS_27) U1.AC1(VSS_56) U1.AC3(VSS_55) U1.AC5(VSS_59) U1.AC9(VSS_65) U1.AC11(VSS_74) U1.AC23(VSS_88) U1.B20(VSS_50) U1.C3(VSS_66) U1.C13(VSS_104) U1.C20(VSS_49) U1.D9(VSS_103) U1.D13(VSS_69) U1.D19(VSS_67) U1.E4(VSS_68) U1.F4(VSS_70) U1.G3(VSS_105) U1.G4(VSS_71) U1.G12(VSS_101) U1.G13(VSS_102) U1.G16(VSS_51) U1.H3(VSS_72) U1.H10(VSS_16) U1.H11(VSS_31) U1.H12(VSS_32) U1.H13(VSS_21) U1.H14(VSS_23) U1.H15(VSS_35) U1.H20(VSS_41) U1.J2(VSS_42) U1.J10(VSS_17) U1.J11(VSS_36) U1.J12(VSS_37) U1.J15(VSS_40) U1.J20(VSS_43) U1.K1(VSS_44) U1.K3(VSS_45) U1.K5(VSS_46) U1.K10(VSS_20) U1.K11(VSS_24) U1.K12(VSS_25) U1.K15(VSS_34) U1.K16(VSS_33) U1.L3(VSS_29) U1.L4(VSS_30) U1.L11(VSS_18) U1.L12(VSS_19) U1.L15(VSS_22) U1.M6(VSS_13) U1.M8(VSS_80) U1.M11(VSS_14) U1.M12(VSS_15) U1.M15(VSS_52) U1.M20(VSS_86) U1.N2(VSS_85) U1.N3(VSS_82) U1.N5(VSS_81) U1.N15(VSS_75) U1.N16(VSS_26) U1.N17(VSS_73) U1.P1(VSS_87) U1.P5(VSS_63) U1.P16(VSS_38) U1.P19(AVSS_PLL) U1.P20(VSS_64) U1.R2(VSS_62) U1.R4(VSS_61) U1.R6(VSS_60) U1.R20(VSS_58) U1.T1(VSS_57) U1.T11(VSS_39) U1.U2(VSS_12) U1.U5(VSS_11) U1.U20(VSS_10) U1.V4(VSS_3) U1.V10(VSS_7) U1.V21(VSS_6) U1.W3(VSS_9) U1.W8(VSS_5) U1.W11(VSS_1) U1.W13(VSS_8) U1.W15(VSS_2) U1.W19(VSS_4) U1.W21(VSS_79) U1.Y1(VSS_78) U1.Y3(VSS_77) U1.Y7(VSS_28) U1.Y9(VSS_76) U1.Y18(VSS_84) U1.Y20(VSS_83) U1.Y23(VSS_53) U2.1(GND) U2.6(RFGND) U3.A1(VSS1) U3.A8(VSS7) U3.B1(VSS2) U3.B2(VSSQ2) U3.B8(VSSQ3) U3.C9(VSSQ4) U3.D1(VSSQ1) U3.D8(VSS8) U3.D9(VSSQ5) U3.F2(VSS6) U3.F8(VSS9) U3.J1(VSS3) U3.J9(VSS10) U3.L1(VSS4) U3.L9(VSS11) U3.N1(VSS5) U3.N9(VSS12) U6.A1(VSS1) U6.A8(VSS7) U6.B1(VSS2) U6.B2(VSSQ2) U6.B8(VSSQ3) U6.C9(VSSQ4) U6.D1(VSSQ1) U6.D8(VSS8) U6.D9(VSSQ5) U6.F2(VSS6) U6.F8(VSS9) U6.J1(VSS3) U6.J9(VSS10) U6.L1(VSS4) U6.L9(VSS11) U6.N1(VSS5) U6.N9(VSS12) U7.1(RFGND1) U7.5(GND) U10.2(GND) U12.2(GND) U19.2(NC2/VSS3) U19.13(VSS1) U19.23(NC14/VSS4) U19.25(NC16/VSS5) U19.36(VSS2) U19.48(NC29/VSS6) U20.A1(VSS1) U20.A8(VSS7) U20.B1(VSS2) U20.B2(VSSQ2) U20.B8(VSSQ3) U20.C9(VSSQ4) U20.D1(VSSQ1) U20.D8(VSS8) U20.D9(VSSQ5) U20.F2(VSS6) U20.F8(VSS9) U20.J1(VSS3) U20.J9(VSS10) U20.L1(VSS4) U20.L9(VSS11) U20.N1(VSS5) U20.N9(VSS12) U21.A1(VSS1) U21.A8(VSS7) U21.B1(VSS2) U21.B2(VSSQ2) U21.B8(VSSQ3) U21.C9(VSSQ4) U21.D1(VSSQ1) U21.D8(VSS8) U21.D9(VSSQ5) U21.F2(VSS6) U21.F8(VSS9) U21.J1(VSS3) U21.J9(VSS10) U21.L1(VSS4) U21.L9(VSS11) U21.N1(VSS5) U21.N9(VSS12) U22.AA4(VSS_8) U22.AA6(VSS_9) U22.K4(VSS_1) U22.M7(VSS_2) U22.P5(VSS_3) U22.R10(VSS_4) U22.U8(VSS_5) U22.Y2(VSS_6) U22.Y5(VSS_7) U28.2(GND) U28.9(SINK) ; also on sheet 3 4 5 6 7 8 15 16 17 18 19
DDR_ADDR0: RN6.1 U3.K3(A0) U6.K3(A0) U20.K3(A0) U21.K3(A0) ; also on sheet 8
DDR_ADDR1: RN4.2 U3.L7(A1) U6.L7(A1) U20.L7(A1) U21.L7(A1) ; also on sheet 8
DDR_ADDR2: RN6.3 U3.L3(A2) U6.L3(A2) U20.L3(A2) U21.L3(A2) ; also on sheet 8
DDR_ADDR3: RN6.2 U3.K2(A3) U6.K2(A3) U20.K2(A3) U21.K2(A3) ; also on sheet 8
DDR_ADDR4: RN4.3 U3.L8(A4) U6.L8(A4) U20.L8(A4) U21.L8(A4) ; also on sheet 8
DDR_ADDR5: RN6.4 U3.L2(A5) U6.L2(A5) U20.L2(A5) U21.L2(A5) ; also on sheet 8
DDR_ADDR6: RN3.1 U3.M8(A6) U6.M8(A6) U20.M8(A6) U21.M8(A6) ; also on sheet 8
DDR_ADDR7: RN2.2 U3.M2(A7) U6.M2(A7) U20.M2(A7) U21.M2(A7) ; also on sheet 8
DDR_ADDR8: RN3.2 U3.N8(A8) U6.N8(A8) U20.N8(A8) U21.N8(A8) ; also on sheet 8
DDR_ADDR9: RN2.3 U3.M3(A9) U6.M3(A9) U20.M3(A9) U21.M3(A9) ; also on sheet 8
DDR_ADDR10: RN7.1 U3.H7(A10/AP) U6.H7(A10/AP) U20.H7(A10/AP) U21.H7(A10/AP) ; also on sheet 8
DDR_ADDR11: RN4.4 U3.M7(A11) U6.M7(A11) U20.M7(A11) U21.M7(A11) ; also on sheet 8
DDR_ADDR12: RN7.4 U3.K7(A12/BC~) U6.K7(A12/BC~) U20.K7(A12/BC~) U21.K7(A12/BC~) ; also on sheet 8
DDR_ADDR13: RN2.1 U3.N3(A13) U6.N3(A13) U20.N3(A13) U21.N3(A13) ; also on sheet 8
DDR_ADDR14: RN3.3 U3.N7(A14) U6.N7(A14) U20.N7(A14) U21.N7(A14) ; also on sheet 8
DDR_ADDR15: RN7.2 U3.J7(A15) U6.J7(A15) U20.J7(A15) U21.J7(A15) ; also on sheet 8
DDR_BA0: RN2.4 U3.J2(BA0) U6.J2(BA0) U20.J2(BA0) U21.J2(BA0) ; also on sheet 8
DDR_BA1: RN4.1 U3.K8(BA1) U6.K8(BA1) U20.K8(BA1) U21.K8(BA1) ; also on sheet 8
DDR_BA2: RN3.4 U3.J3(BA2) U6.J3(BA2) U20.J3(BA2) U21.J3(BA2) ; also on sheet 8
DDR_CASN: RN5.2 U3.G3(~{CAS}) U6.G3(~{CAS}) U20.G3(~{CAS}) U21.G3(~{CAS}) ; also on sheet 8
DDR_CKE: RN5.4 U3.G9(CKE) U6.G9(CKE) U20.G9(CKE) U21.G9(CKE) ; also on sheet 8
DDR_CLK1N: RN1.4 U3.G7(~{CK}) U6.G7(~{CK}) U20.G7(~{CK}) U21.G7(~{CK}) ; also on sheet 8
DDR_CLK1P: RN1.3 U3.F7(CK) U6.F7(CK) U20.F7(CK) U21.F7(CK) ; also on sheet 8
DDR_CSN: R33.1(A) U3.H2(~{CS}) U6.H2(~{CS}) U20.H2(~{CS}) U21.H2(~{CS}) ; also on sheet 8
DDR_DM0: U3.B7(DM/TDQS) ; also on sheet 8
DDR_DM1: U6.B7(DM/TDQS) ; also on sheet 8
DDR_DM2: U21.B7(DM/TDQS) ; also on sheet 8
DDR_DM3: U20.B7(DM/TDQS) ; also on sheet 8
DDR_DQ0: U3.B3(DQ0) ; also on sheet 8
DDR_DQ1: U3.C7(DQ1) ; also on sheet 8
DDR_DQ2: U3.C2(DQ2) ; also on sheet 8
DDR_DQ3: U3.C8(DQ3) ; also on sheet 8
DDR_DQ4: U3.E3(DQ4) ; also on sheet 8
DDR_DQ5: U3.E8(DQ5) ; also on sheet 8
DDR_DQ6: U3.D2(DQ6) ; also on sheet 8
DDR_DQ7: U3.E7(DQ7) ; also on sheet 8
DDR_DQ8: U6.B3(DQ0) ; also on sheet 8
DDR_DQ9: U6.C7(DQ1) ; also on sheet 8
DDR_DQ10: U6.C2(DQ2) ; also on sheet 8
DDR_DQ11: U6.C8(DQ3) ; also on sheet 8
DDR_DQ12: U6.E3(DQ4) ; also on sheet 8
DDR_DQ13: U6.E8(DQ5) ; also on sheet 8
DDR_DQ14: U6.D2(DQ6) ; also on sheet 8
DDR_DQ15: U6.E7(DQ7) ; also on sheet 8
DDR_DQ16: U21.B3(DQ0) ; also on sheet 8
DDR_DQ17: U21.C7(DQ1) ; also on sheet 8
DDR_DQ18: U21.C2(DQ2) ; also on sheet 8
DDR_DQ19: U21.C8(DQ3) ; also on sheet 8
DDR_DQ20: U21.E3(DQ4) ; also on sheet 8
DDR_DQ21: U21.E8(DQ5) ; also on sheet 8
DDR_DQ22: U21.D2(DQ6) ; also on sheet 8
DDR_DQ23: U21.E7(DQ7) ; also on sheet 8
DDR_DQ24: U20.B3(DQ0) ; also on sheet 8
DDR_DQ25: U20.C7(DQ1) ; also on sheet 8
DDR_DQ26: U20.C2(DQ2) ; also on sheet 8
DDR_DQ27: U20.C8(DQ3) ; also on sheet 8
DDR_DQ28: U20.E3(DQ4) ; also on sheet 8
DDR_DQ29: U20.E8(DQ5) ; also on sheet 8
DDR_DQ30: U20.D2(DQ6) ; also on sheet 8
DDR_DQ31: U20.E7(DQ7) ; also on sheet 8
DDR_DQS0N: U3.D3(~{DQS}) ; also on sheet 8
DDR_DQS0P: U3.C3(DQS) ; also on sheet 8
DDR_DQS1N: U6.D3(~{DQS}) ; also on sheet 8
DDR_DQS1P: U6.C3(DQS) ; also on sheet 8
DDR_DQS2N: U21.D3(~{DQS}) ; also on sheet 8
DDR_DQS2P: U21.C3(DQS) ; also on sheet 8
DDR_DQS3N: U20.D3(~{DQS}) ; also on sheet 8
DDR_DQS3P: U20.C3(DQS) ; also on sheet 8
DDR_ODT: RN5.3 U3.G1(ODT) U6.G1(ODT) U20.G1(ODT) U21.G1(ODT) ; also on sheet 8
DDR_RASN: RN5.1 U3.F3(~{RAS}) U6.F3(~{RAS}) U20.F3(~{RAS}) U21.F3(~{RAS}) ; also on sheet 8
DDR_RESETN: C298.1(A) C299.1(A) C300.1(A) C301.1(A) R46.1(A) U3.N2(~{RESET}) U6.N2(~{RESET}) U20.N2(~{RESET}) U21.N2(~{RESET}) ; also on sheet 8
DDR_VREF_A: C49.1(A) C210.2(B) C211.1(A) R123.2(B) R124.1(A) U3.E1(VREFDQ) U3.J8(VREFCA)
DDR_VREF_B: C66.1(A) C202.2(B) C203.1(A) R84.2(B) R103.1(A) U6.E1(VREFDQ) U6.J8(VREFCA)
DDR_VREF_C: C86.1(A) C234.2(B) C235.1(A) R133.2(B) R139.1(A) U21.E1(VREFDQ) U21.J8(VREFCA)
DDR_VREF_D: C87.1(A) C224.2(B) C225.1(A) R129.2(B) R130.1(A) U20.E1(VREFDQ) U20.J8(VREFCA)
DDR_VTT: C118.1(A) C184.1(A) C190.1(A) C191.1(A) C201.1(A) C271.1(A) C292.1(A) C293.1(A) C295.1(A) C302.1(A) C303.1(A) C304.1(A) R17.2(B) R33.2(B) R78.2(B) RN1.5 RN1.6 RN2.5 RN2.6 RN2.7 RN2.8 RN3.5 RN3.6 RN3.7 RN3.8 RN4.5 RN4.6 RN4.7 RN4.8 RN5.5 RN5.6 RN5.7 RN5.8 RN6.5 RN6.6 RN6.7 RN6.8 RN7.5 RN7.6 RN7.7 RN7.8 U28.4(VOUT)
DDR_WEN: R17.1(A) U3.H3(~{WE}) U6.H3(~{WE}) U20.H3(~{WE}) U21.H3(~{WE}) ; also on sheet 8
MOS_CTRL: Q8.1(G) ; also on sheet 5
NF_ALE_EMMC_PWREN: U19.17(ALE) ; also on sheet 6
NF_CLE: U19.16(CLE) ; also on sheet 6
NF_CSN0_EMMC_CMD: R212.2(B) U19.9(~{CE}) U22.W5(CMD) ; also on sheet 6
NF_DQ0_EMMC_D0: R189.2(B) U19.29(I/O0) U22.H3(DAT0) ; also on sheet 6
NF_DQ1_EMMC_D1: R12.2(B) U19.30(I/O1) U22.H4(DAT1) ; also on sheet 6
NF_DQ2_EMMC_D2: R29.2(B) U19.31(I/O2) U22.H5(DAT2) ; also on sheet 6
NF_DQ3_EMMC_D3: R58.2(B) U19.32(I/O3) U22.J2(DAT3) ; also on sheet 6
NF_DQ4_EMMC_D4: R176.2(B) U19.41(I/O4) U22.J3(DAT4) ; also on sheet 6
NF_DQ5_EMMC_D5: R177.2(B) U19.42(I/O5) U22.J4(DAT5) ; also on sheet 6
NF_DQ6_EMMC_D6: R188.2(B) U19.43(I/O6) U22.J5(DAT6) ; also on sheet 6
NF_DQ7_EMMC_D7_BOOT_SEL0: R202.2(B) U19.44(I/O7) U22.J6(DAT7) ; also on sheet 6
NF_RDY0_EMMC_RST: C115.1(A) R203.2(B) U19.7(R/B~) U22.U5(RSTN) ; also on sheet 6
NF_REN_EMMC_CLK: U19.8(~{RE}) U22.W6(CLK) ; also on sheet 6
NF_WEN_EMMC_DET: U19.18(~{WE}) ; also on sheet 6
NF_WP: R89.1(A) R215.2(B) U19.19(~{WP})
RF0: C64.1(A) L1.2(B) U7.3(RF0)
RF1: C50.1(A) L7.2(B) U2.7(RF) U7.2(RF1)
RFF0: C61.1(A) J5.1 L1.1(A)
RFF1: C60.1(A) J4.1 L7.1(A)
USB0_DM: C119.1(A) D6.1(A) J12.2 ; also on sheet 7
USB0_DP: C113.1(A) D1.1(A) J12.3 ; also on sheet 7
USB1_DM: J2.4(D-) U2.4(DM) U7.7(DM) ; also on sheet 7
USB1_DP: J2.3(D+) U2.2(DP) U7.6(DP) ; also on sheet 7
USB3_DM: J13.2(D-) ; also on sheet 6
USB3_DP: J13.3(D+) ; also on sheet 6
USB3_RXN: J13.5(RX-) ; also on sheet 6
USB3_RXP: J13.6(RX+) ; also on sheet 6
USB3_TXN: C77.2(B) ; also on sheet 6
USB3_TXP: C81.2(B) ; also on sheet 6
N03644: R42.2(B) U12.4(ILIM)
N03926: R16.1(A) U12.3(EN)
N03950: R41.2(B) U10.4(ILIM)
N03956: R15.1(A) U10.3(EN)
N03990: C29.1(A) C52.1(A) J12.1 LB2.1 U10.5(OUT)
N04006: C38.1(A) C75.1(A) J13.1(VBUS) LB3.1 U12.5(OUT)
N05486: R68.1(A) U19.39(NC24)
N07144: R71.2(B) U21.H8(ZQ)
N07188: R75.2(B) U20.H8(ZQ)
N09178: R55.2(B) U6.H8(ZQ)
N09250: R54.2(B) U3.H8(ZQ)
N11323: C196.1(A) Q8.3(D) R11.2(B) R24.1(A) U28.3(REFEN)
N12433: C255.2(B) U1.T19(DVDD11_LDO_DECAP)
N3765204: C123.1(A) C124.1(A) U22.K2(VDDI)
N16753488: C81.1(A) J13.9(TX+)
N16753490: C77.1(A) J13.8(TX-)
N16877370: R80.2(B) U19.38(NC23/VDDQ2)

Not connected (* = marked no-connect by the designer): J2 1(NC1)* 6(NC2)* 8(RF0)* 11(RF1)*; RN1 1* 2* 7* 8*; RN7 3*; U2 3(VDD+)*; U3 A3(NC3)* A7(NU/TDQS~)* F1(NC1)* F9(NC4)* H1(NC2)* H9(NC5)*; U6 A3(NC3)* A7(NU/TDQS~)* F1(NC1)* F9(NC4)* H1(NC2)* H9(NC5)*; U7 4(XI)* 9(SUSPEND)* 10(WO_WLAN)*; U19 3(NC3)* 4(NC4)* 5(NC5)* 6(NC6)* 10(NC7)* 11(NC8)* 14(NC9)* 15(NC10)* 20(NC11)* 21(NC12)* 22(NC13)* 26(NC17) 27(NC18) 28(NC19) 33(NC20) 35(NC22)* 40(NC25) 45(NC26) 46(NC27) 47(NC28); U20 A3(NC3)* A7(NU/TDQS~)* F1(NC1)* F9(NC4)* H1(NC2)* H9(NC5)*; U21 A3(NC3)* A7(NU/TDQS~)* F1(NC1)* F9(NC4)* H1(NC2)* H9(NC5)*; U22 A4(NC_1)* A6(NC_2)* A9(NC_3)* A11(NC_4)* AA1(NC_122)* AA2(NC_123)* AA7(NC_124)* AA8(NC_125)* AA9(NC_126)* AA10(NC_127)* AA11(NC_128)* AA12(NC_129)* AA13(NC_130)* AA14(NC_131)* AE1(NC_132)* AE14(NC_133)* AG2(NC_134)* AG13(NC_135)* AH4(NC_136)* AH6(NC_137)* AH9(NC_138)* AH11(NC_95)* B2(NC_5)* B13(NC_6)* D1(NC_7)* D14(NC_8)* H1(NC_9)* H2(NC_10)* H6(NC_11)* H7(NC_12)* H8(NC_13)* H9(NC_14)* H10(NC_15)* H11(NC_16)* H12(NC_17)* H13(NC_18)* H14(NC_19)* J1(NC_20)* J7(NC_21)* J8(NC_22)* J9(NC_23)* J10(NC_24)* J11(NC_25)* J12(NC_26)* J13(NC_27)* J14(NC_28)* K1(NC_29)* K3(NC_30)* K5(NC_31)* K7(NC_32)* K8(NC_33)* K9(NC_34)* K10(NC_35)* K11(NC_36)* K12(NC_37)* K13(NC_38)* K14(NC_39)* L1(NC_40)* L2(NC_41)* L3(NC_42)* L4(A1)* L12(NC_43)* L13(NC_44)* L14(NC_45)* M1(NC_46)* M2(NC_47)* M3(NC_48)* M5(NC_49)* M8(NC_50)* M9(NC_51)* M10(NC_52)* M12(NC_53)* M13(NC_54)* M14(NC_55)* N1(NC_56)* N2(NC_57)* N3(NC_58)* N10(NC_59)* N12(NC_60)* N13(NC_61)* N14(NC_62)* P1(NC_63)* P2(NC_64)* P3(NC_65)* P10(NC_66)* P12(NC_67)* P13(NC_68)* P14(NC_69)* R1(NC_70)* R2(NC_71)* R3(NC_72)* R5(NC_73)* R12(NC_74)* R13(NC_75)* R14(NC_76)* T1(NC_77)* T2(NC_78)* T3(NC_79)* T5(NC_80)* T12(NC_81)* T13(NC_82)* T14(NC_83)* U1(NC_84)* U2(NC_85)* U3(NC_86)* U6(NC_87)* U7(NC_88)* U10(NC_89)* U12(NC_90)* U13(NC_91)* U14(NC_92)* V1(NC_93)* V2(NC_94)* V3(NC_96)* V12(NC_97)* V13(NC_98)* V14(NC_99)* W1(NC_100)* W2(NC_101)* W3(NC_102)* W7(NC_103)* W8(NC_104)* W9(NC_105)* W10(NC_106)* W11(NC_107)* W12(NC_108)* W13(NC_109)* W14(NC_110)* Y1(NC_111)* Y3(NC_112)* Y6(NC_113)* Y7(NC_114)* Y8(NC_115)* Y9(NC_116)* Y10(NC_117)* Y11(NC_118)* Y12(NC_119)* Y13(NC_120)* Y14(NC_121)*; U28 5(NC1)* 7(NC2)* 8(NC3)*

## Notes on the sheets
sheet 9
- Unit 4 of Hi3798MV100(POWER)
sheet 10
- Unit 5 of Hi3798MV100(VSS)
sheet 11
- DDRA
- 1%
- 1%
- Close to VIA
- 1%
- 1%
- 1%
- 1%
sheet 12
- DDRB
- 1%
- 1%
- 1%
- 1%
- 1%
- 1%
sheet 13
- NAND FLASH/EMMC
- NAND FLASH
- eMMC/fSD
- fSD  10K
- fSD
- 4GB
- H6 eMMC5.0
- NFWP
- 0:Protect
- 1:NOT Protect
- 4GB
- NAND FLASH
- C142=C143=100NF,C36=1UF,R215=4.7K,R68=0,C92=100UF,D4=DIODE,U19=NAND
- others=NC,If use MICRON NAND FLASH,R68=NC
- eMMC
- C63=C123=C124=C93=C105=C323=C324=100NF,C275=2.2UF
- T5 eMMC5.0
- R203=R189=R12=R29=R58=R176=R177=R188=R202=47K,R212=10K,R92=0,U22=eMMC,others=NC
- fSD
- Pay attention to pin38&pin39,these pins are NC for the MLC NAND of some
- C63=C123=C124=C93=C105=C323=C324=100NF,C275=2.2UF
- brands(such as Micron),but it should be connected to the VCC of
- R203=R189=R12=R29=R58=R212=10K,R92=0,U22=fSD,others=NC
- others(such as Toshiba and Hynix).
- R5 eMMC5.0
- Pls refer to the corresponding datasheet for detail.
sheet 14
- USB2.0/USB3.0/WIFI
- ETA6010:Current=1.3A
- USB0:usb_boot/adb
- For Board Antenna
- ANTF:50ohm Resistance
- ETA6010:Current=1.3A
- For Board Antenna
- ANTF:50ohm Resistance
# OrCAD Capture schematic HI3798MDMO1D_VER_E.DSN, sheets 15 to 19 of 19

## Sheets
15 SHEET15: size Custom
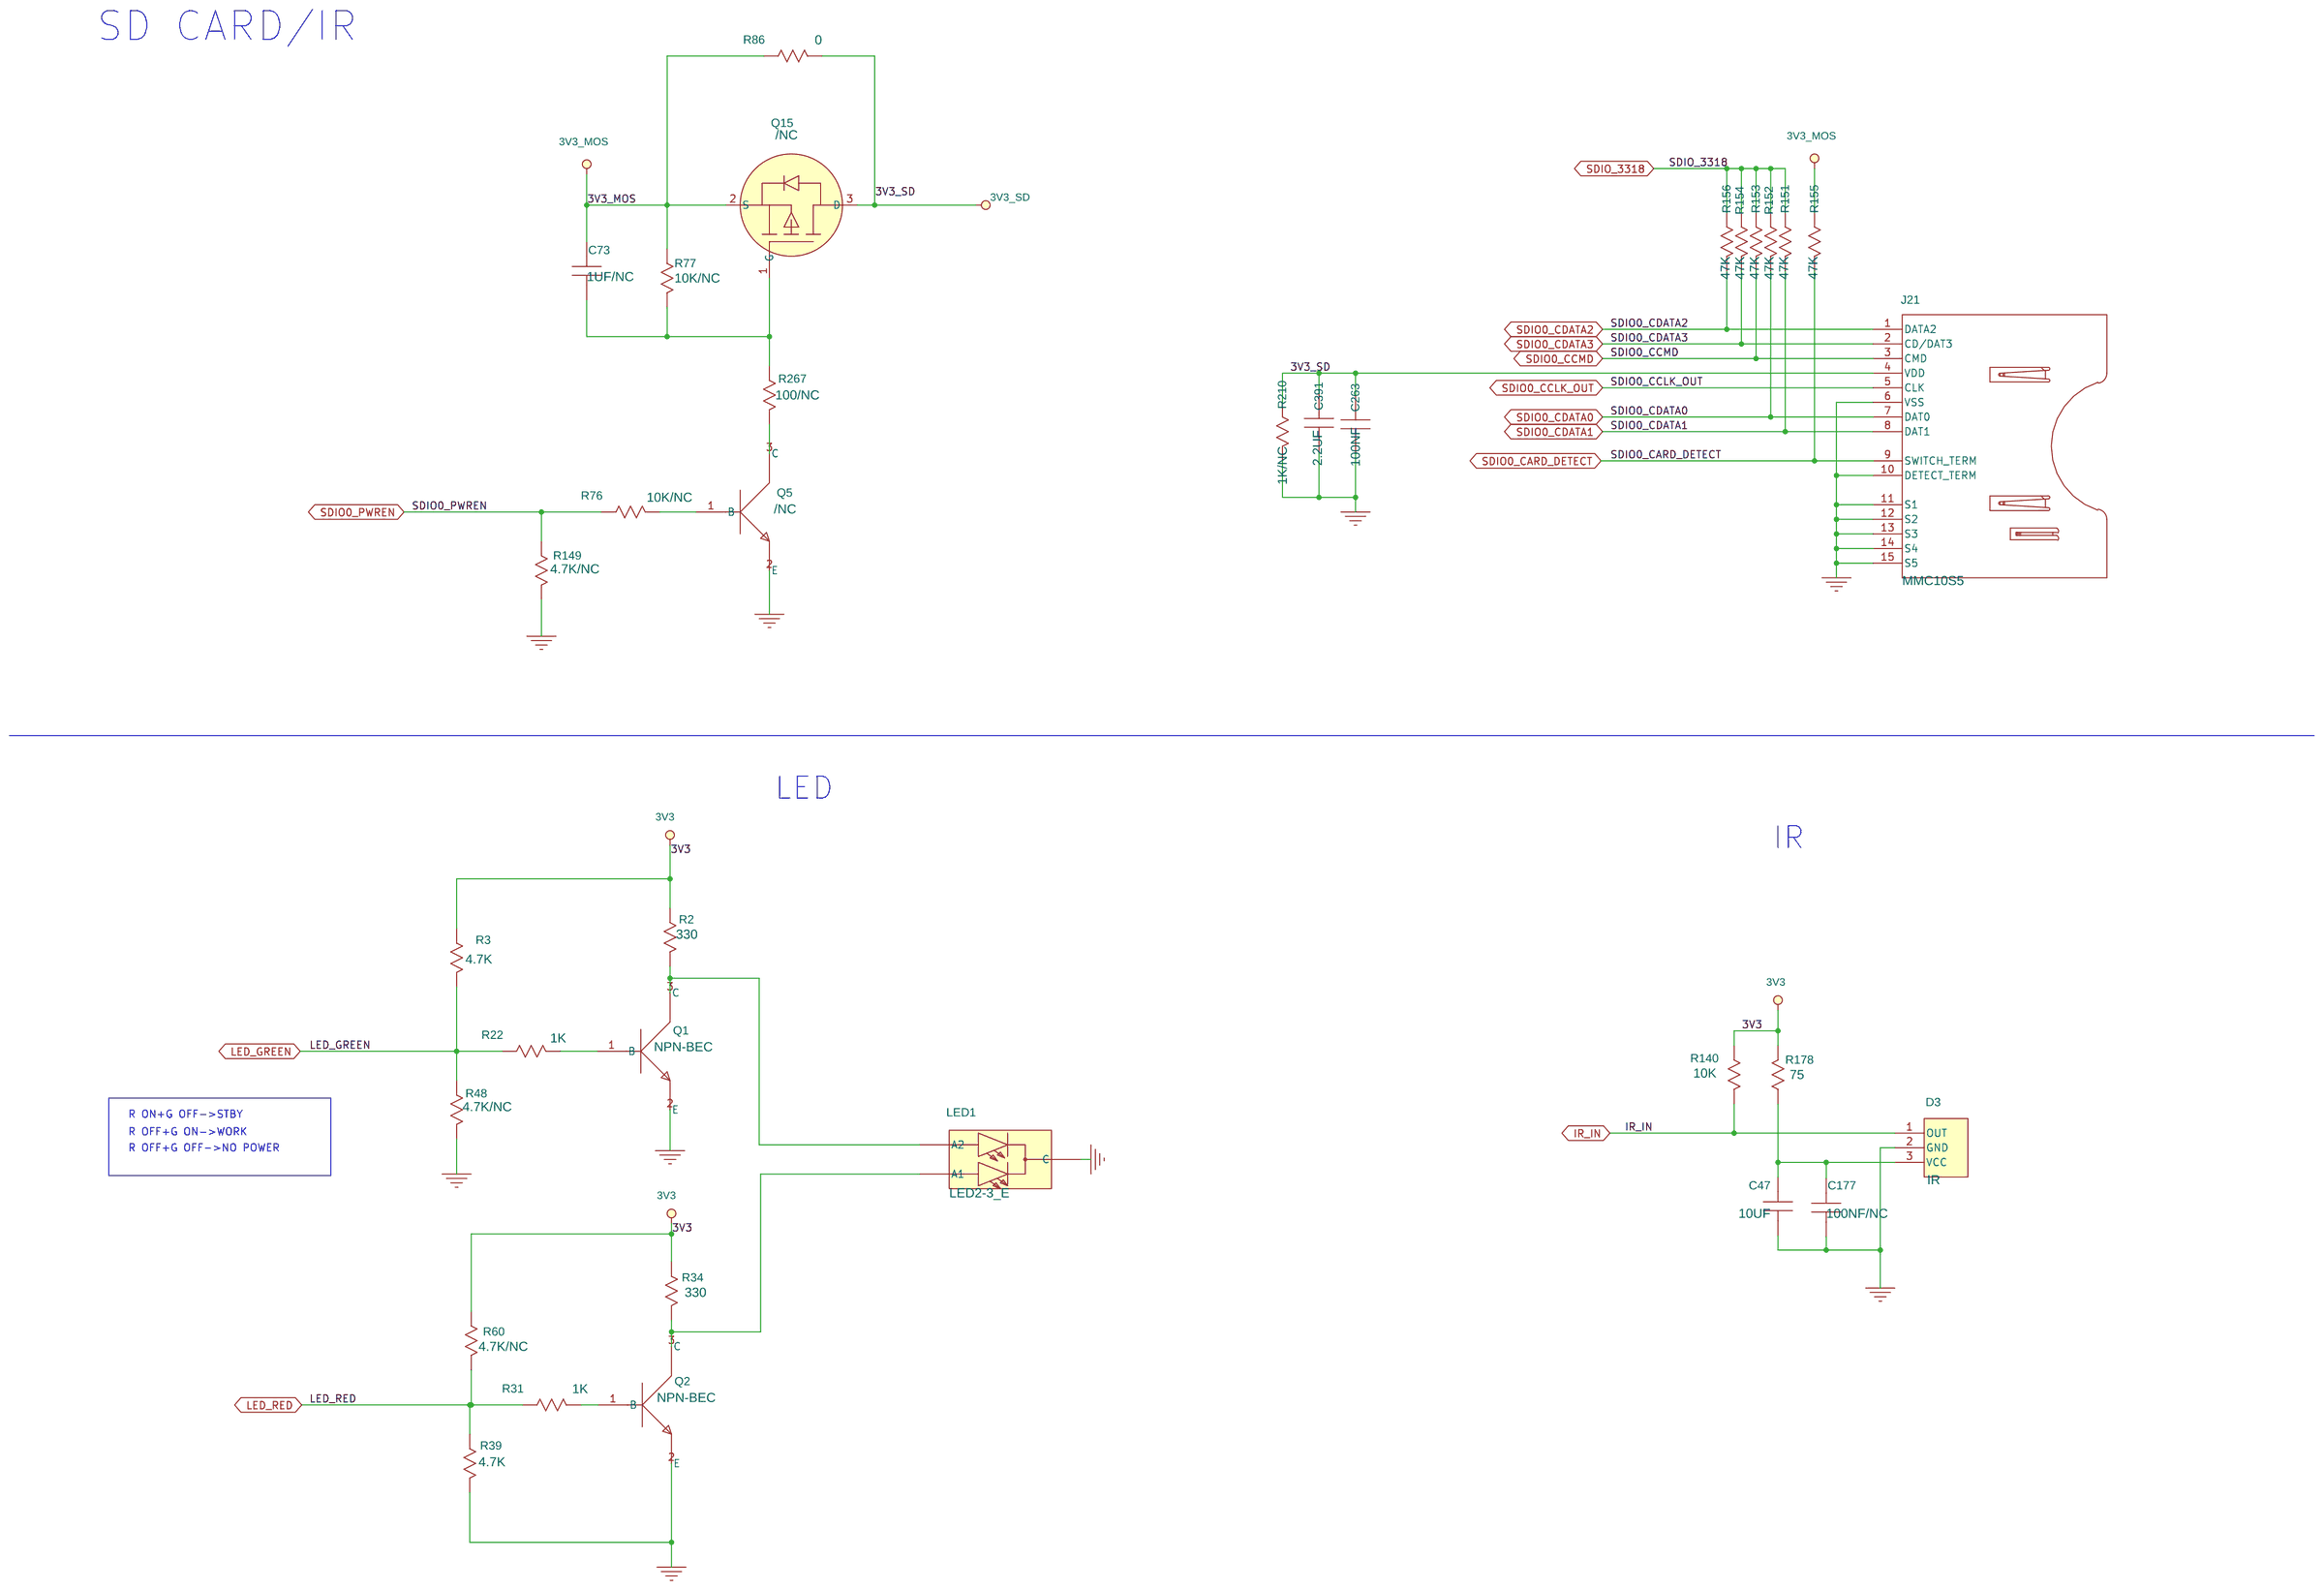
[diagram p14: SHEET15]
16 SHEET16: size Custom
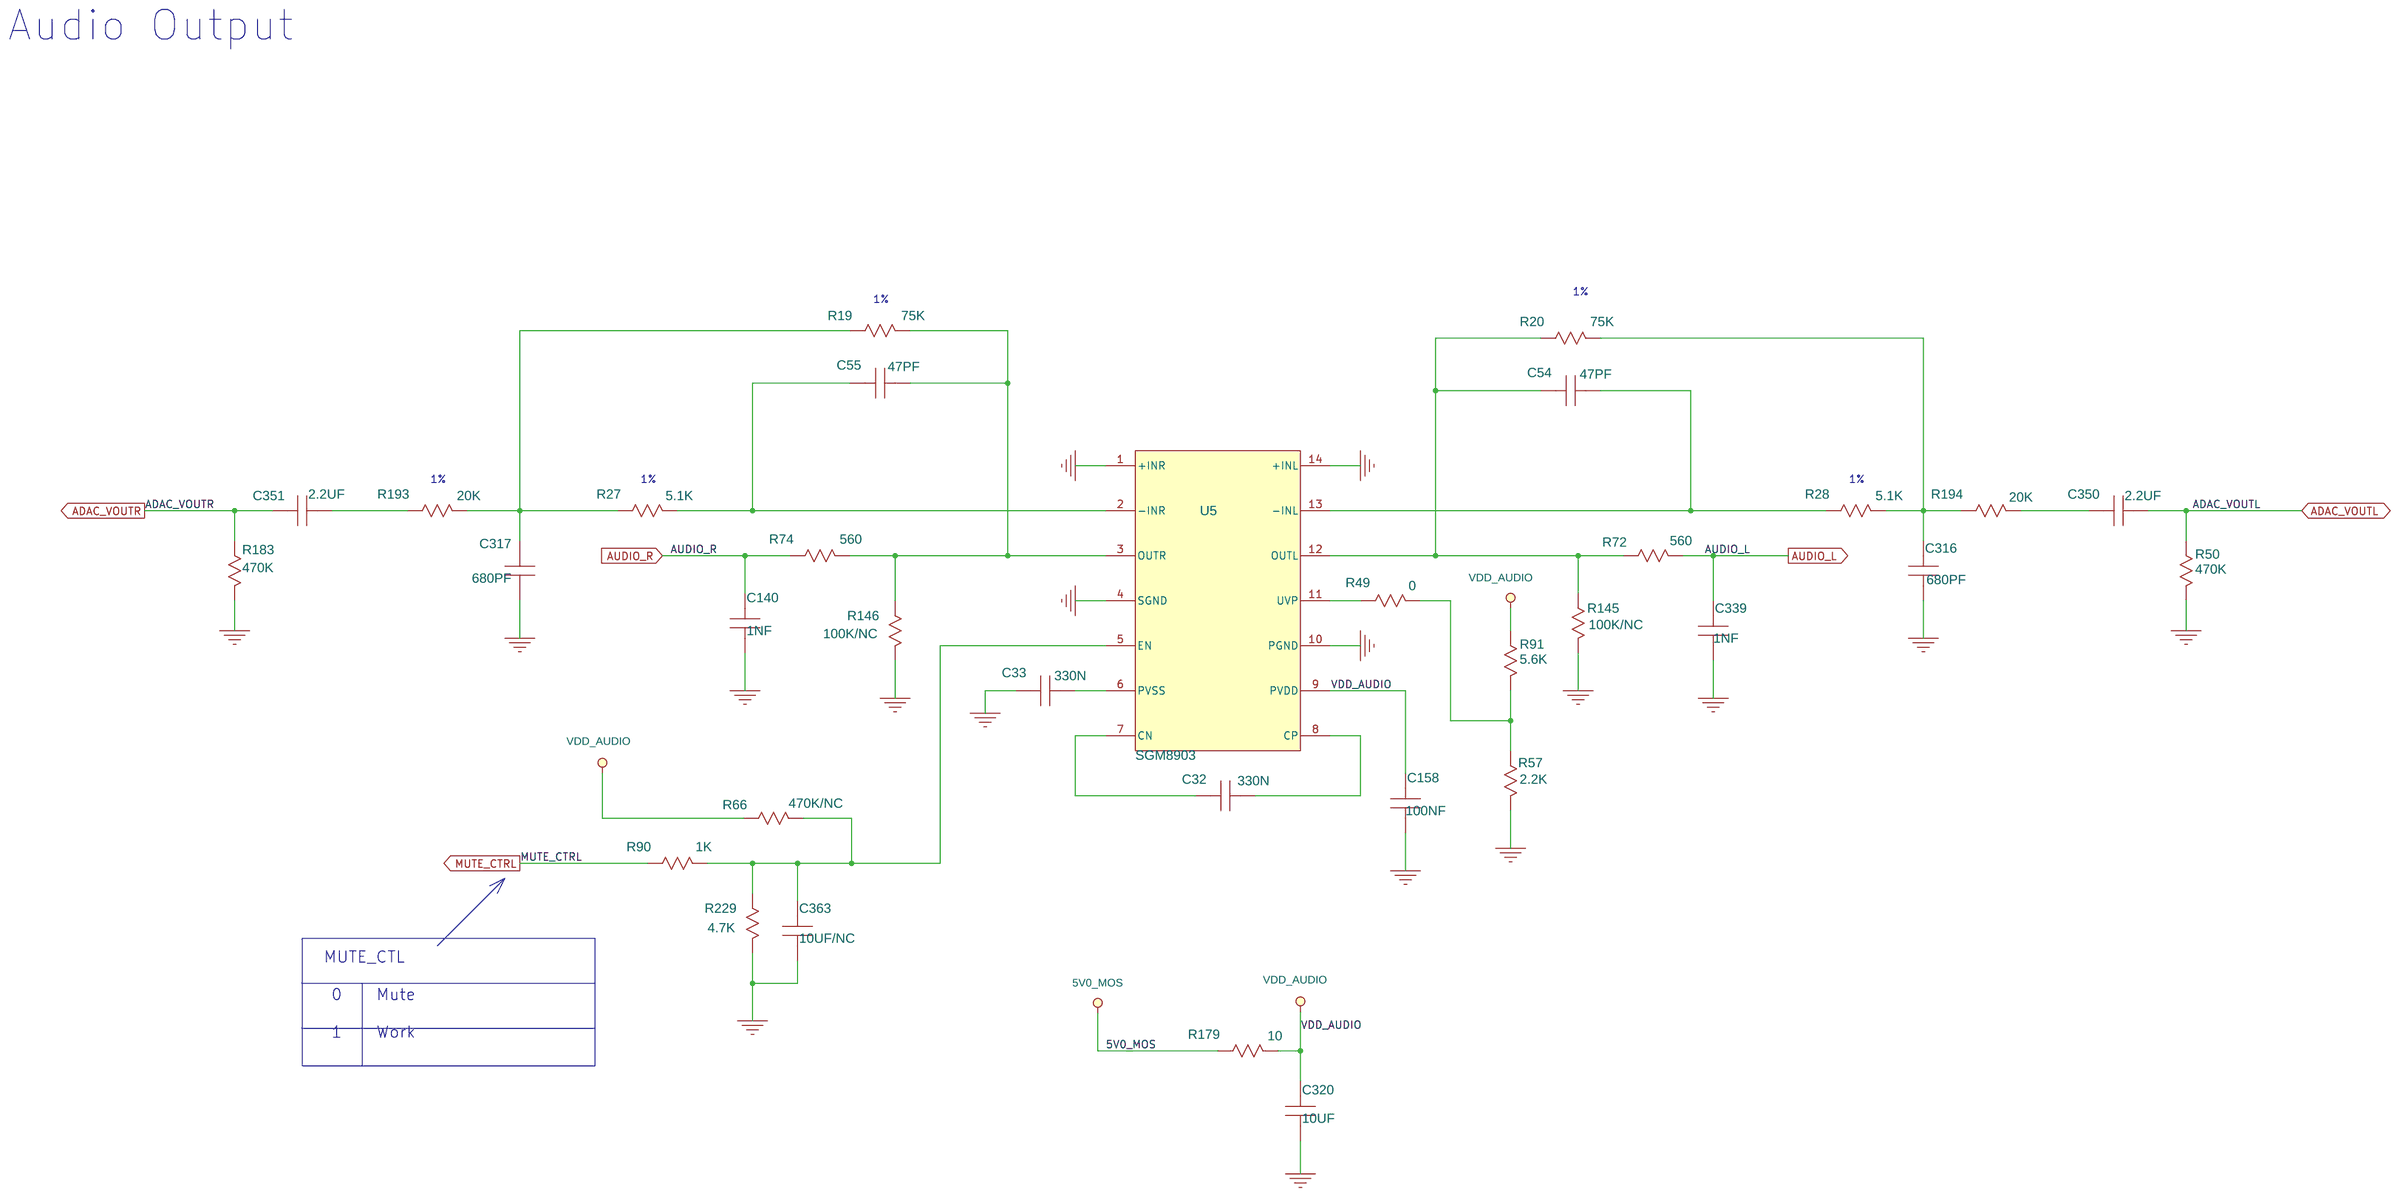
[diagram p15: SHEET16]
17 SHEET17: size Custom
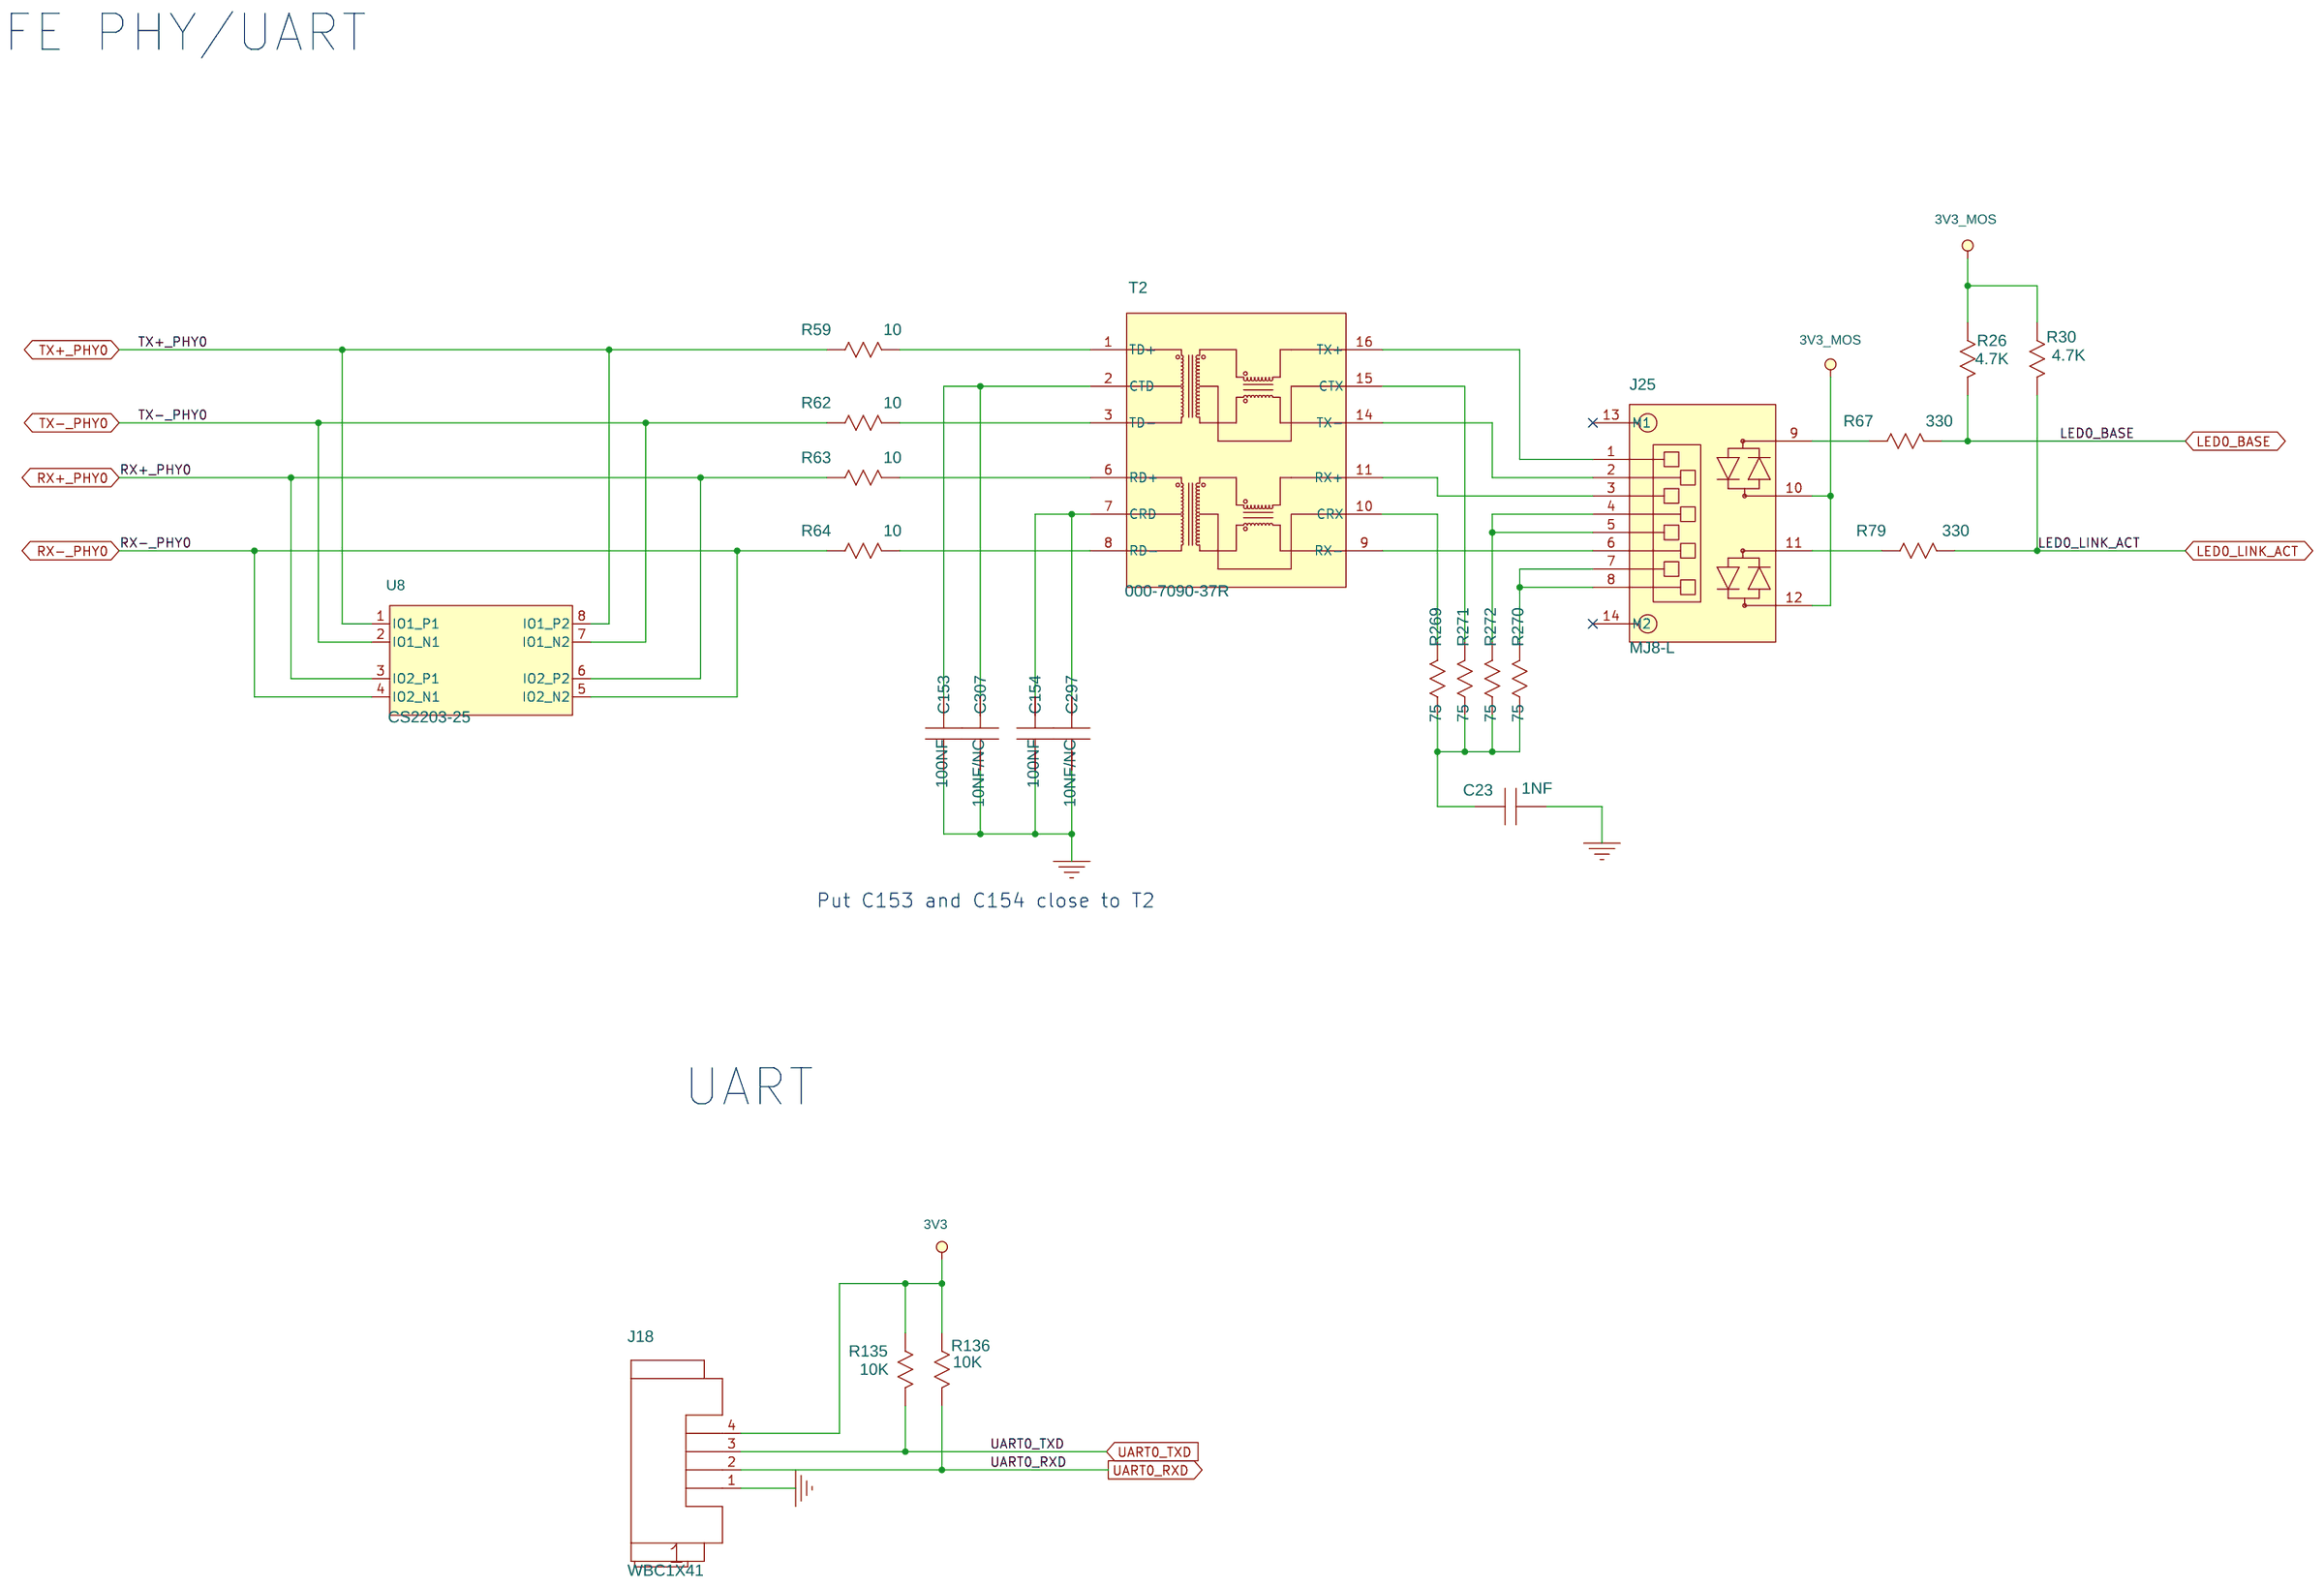
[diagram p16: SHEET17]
18 SHEET18: size A
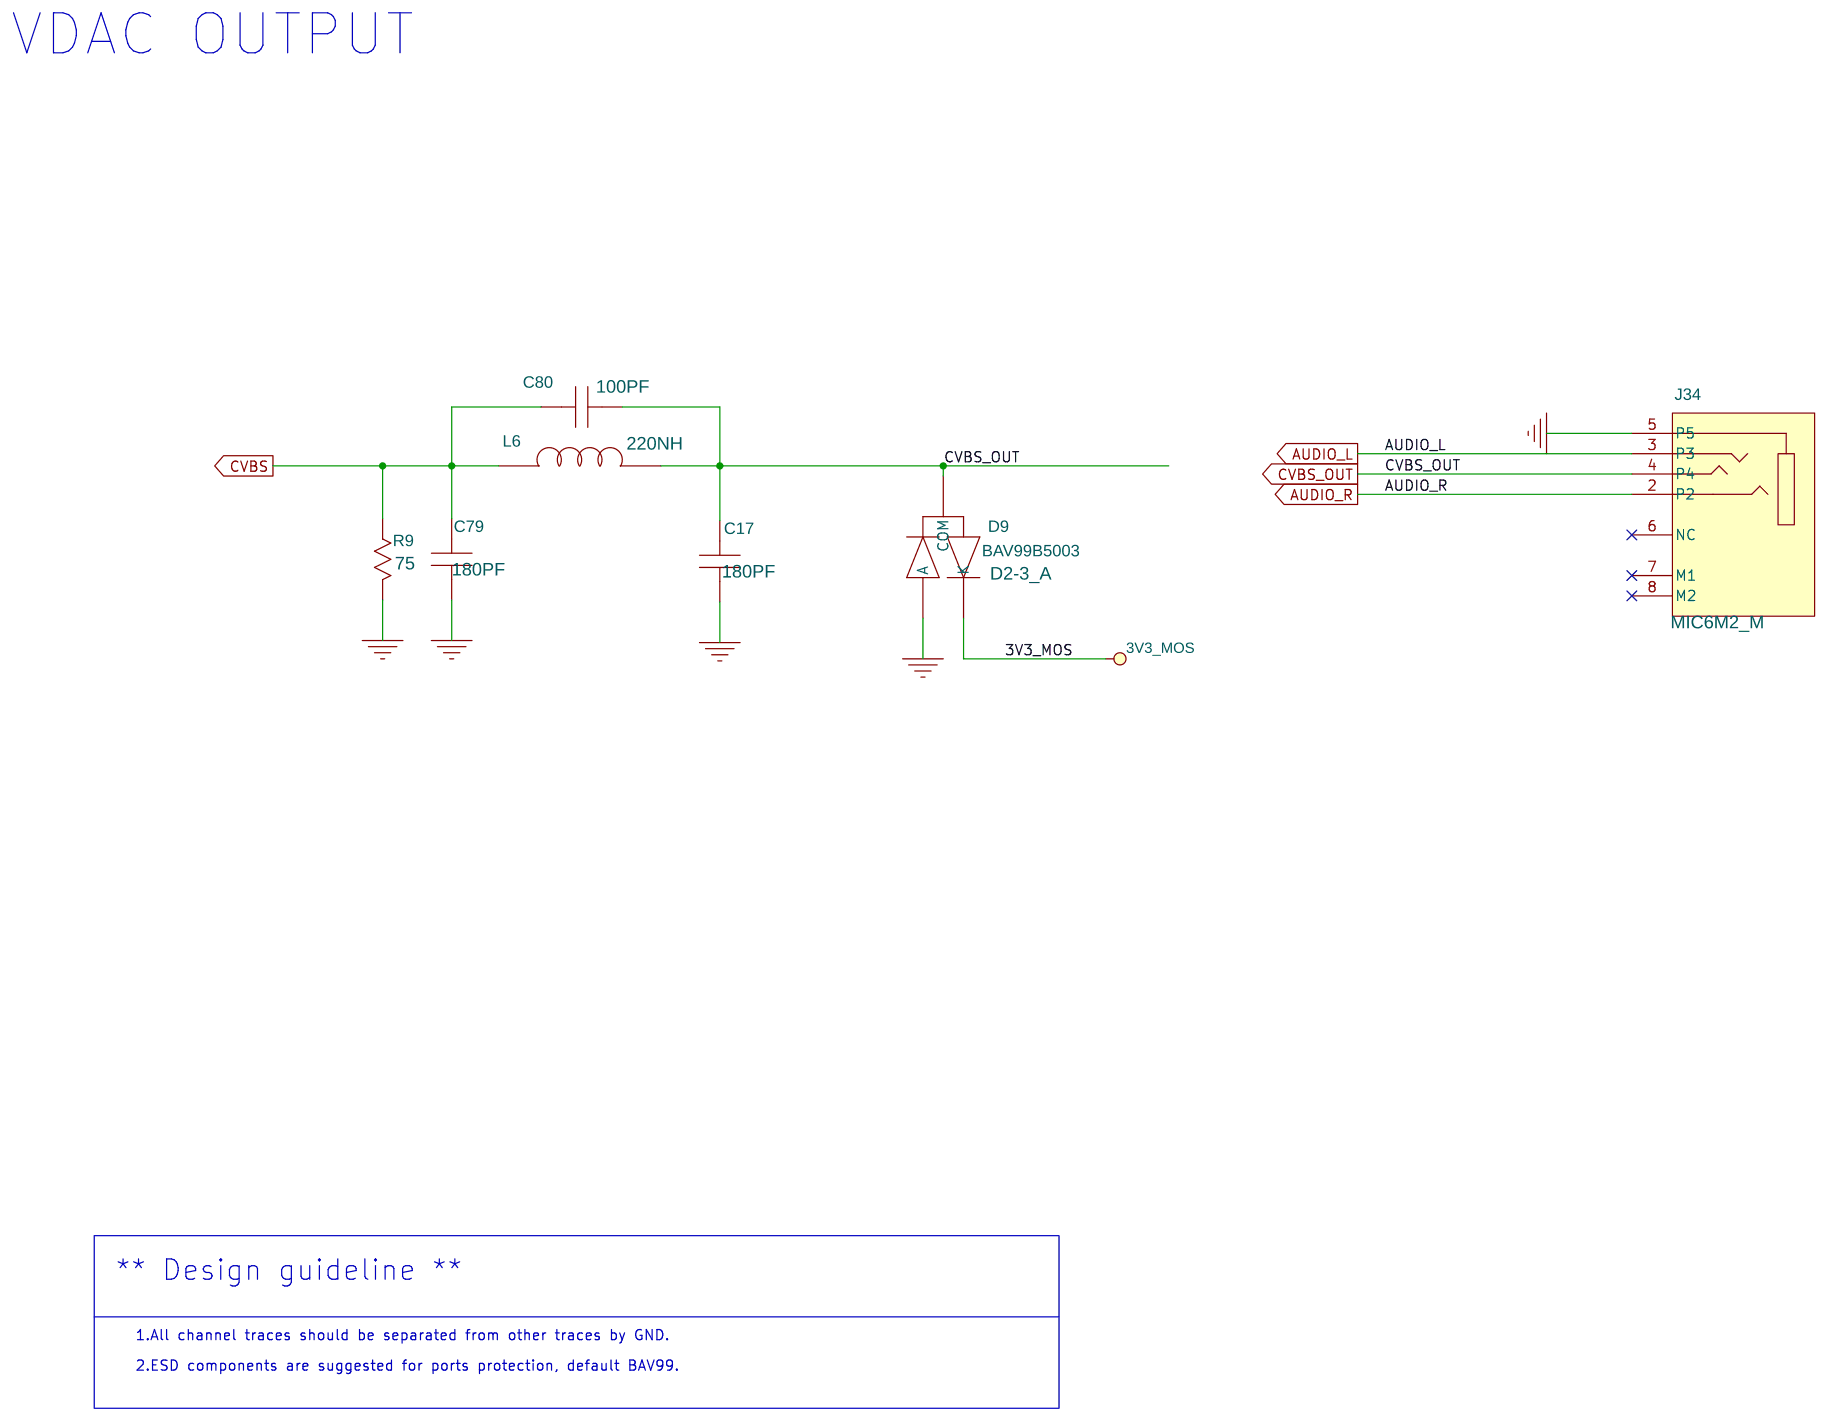
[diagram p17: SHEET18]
19 SHEET19: size Custom

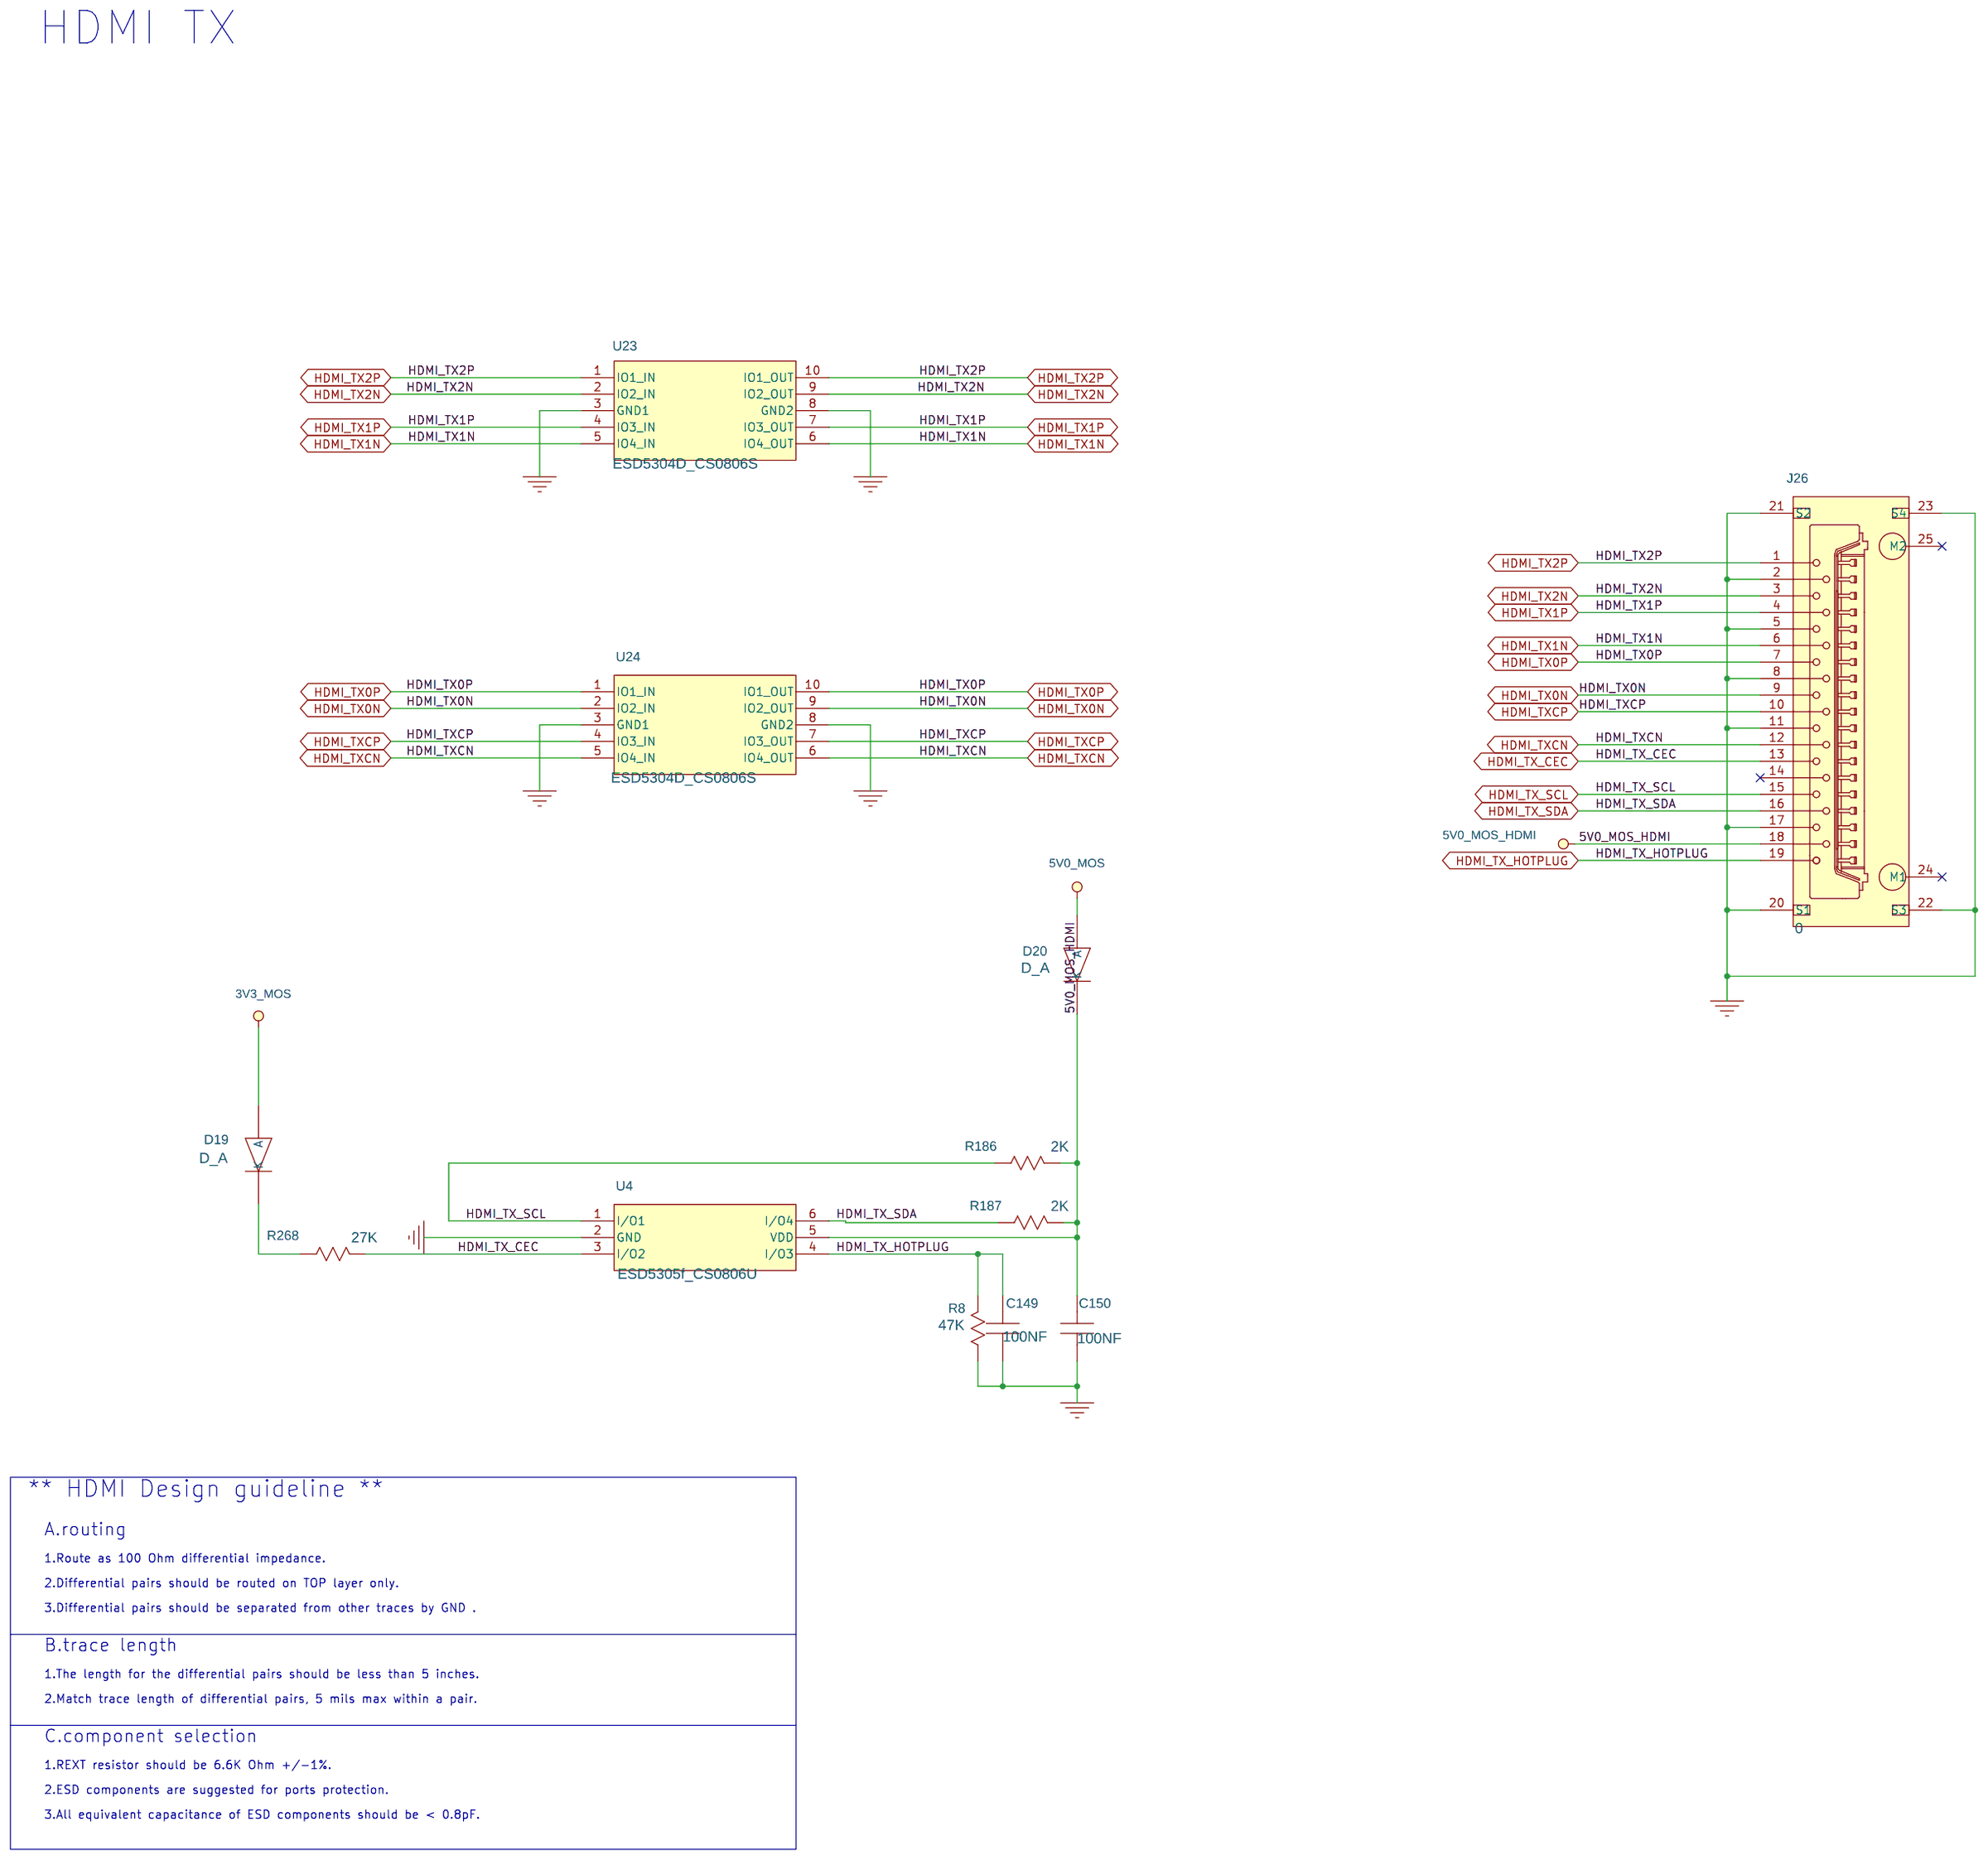
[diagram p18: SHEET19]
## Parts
sheet SHEET15
C47  10UF  [SC0603]
C73  1UF/NC  [SC0402]
C177  100NF/NC  [SC0402]
C263  100NF  [SC0603]
C391  2.2UF  [SC0603]
D3  IR  [SEN3-100C]
J21  MMC10S5  [MICRO_SD8-PUSH]
LED1  LED2-3_E  [LED3C-100C]
Q1  NPN-BEC  [SOT23]
Q2  NPN-BEC  [SOT23]
Q5  /NC  [SOT23]
Q15  /NC  [SOT23]
R2  330  [SR0402]
R3  4.7K  [SR0402]
R22  1K  [SR0402]
R31  1K  [SR0402]
R34  330  [SR0402]
R39  4.7K  [SR0402]
R48  4.7K/NC  [SR0402]
R60  4.7K/NC  [SR0402]
R76  10K/NC  [SR0603]
R77  10K/NC  [SR0603]
R86  0  [SR0603]
R140  10K  [SR0402]
R149  4.7K/NC  [SR0603]
R151  47K  [SR0402]
R152  47K  [SR0402]
R153  47K  [SR0402]
R154  47K  [SR0402]
R155  47K  [SR0402]
R156  47K  [SR0402]
R178  75  [SR0402]
R210  1K/NC  [SR0603]
R267  100/NC  [SR0603]
sheet SHEET16
C32  330N  [HSC0402]
C33  330N  [HSC0402]
C54  47PF  [SC0402]
C55  47PF  [SC0402]
C140  1NF  [SC0402]
C158  100NF  [SC0402]
C316  680PF  [SC0402]
C317  680PF  [SC0402]
C320  10UF  [SC0603]
C339  1NF  [SC0402]
C350  2.2UF  [SC0603]
C351  2.2UF  [SC0603]
C363  10UF/NC  [SC0603]
R19  75K  [SR0603]
R20  75K  [SR0603]
R27  5.1K  [SR0603]
R28  5.1K  [SR0603]
R49  0  [SR0402]
R50  470K  [SR0402]
R57  2.2K  [SR0402]
R66  470K/NC  [SR0402]
R72  560  [HSR0402]
R74  560  [HSR0402]
R90  1K  [SR0402]
R91  5.6K  [SR0402]
R145  100K/NC  [SR0402]
R146  100K/NC  [SR0402]
R179  10  [SR0603]
R183  470K  [SR0402]
R193  20K  [SR0402]
R194  20K  [SR0402]
R229  4.7K  [SR0402]
U5  SGM8903  [SGM8903]
sheet SHEET17
C23  1NF  [SC1206]
C153  100NF  [SC0402]
C154  100NF  [SC0402]
C297  10NF/NC  [SC0402]
C307  10NF/NC  [SC0402]
J18  WBC1X41  [WBC0104-49T]
J25  MJ8-L  [MJ8-RLY]
R26  4.7K  [SR0402]
R30  4.7K  [SR0402]
R59  10  [SR0402]
R62  10  [SR0402]
R63  10  [SR0402]
R64  10  [SR0402]
R67  330  [SR0402]
R79  330  [SR0402]
R135  10K  [SR0402]
R136  10K  [SR0402]
R269  75  [SR0805]
R270  75  [SR0805]
R271  75  [SR0805]
R272  75  [SR0805]
T2  000-7090-37R  [STFM16-50-285]
U8  CS2203-25  [RN8-0402]
sheet SHEET18
C17  180PF  [SC0402]
C79  180PF  [SC0402]
C80  100PF  [SC0402]
D9  D2-3_A  [SOT23]
J34  MIC6M2_M  [VAF6-1107]
L6  220NH  [SL0402]
R9  75  [SR0402]
sheet SHEET19
C149  100NF  [SC0402]
C150  100NF  [SC0402]
D19  D_A  [HSOD323A]
D20  D_A  [HSOD323A]
J26  0  [WBC0119-20R-A]
R8  47K  [SR0402]
R186  2K  [SR0402]
R187  2K  [SR0402]
R268  27K  [SR0402]
U4  ESD5305f_CS0806U  [SOT23A-6L]
U23  ESD5304D_CS0806S  [DFN2510P10E]
U24  ESD5304D_CS0806S  [DFN2510P10E]

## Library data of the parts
C47 C320 C363 = C: %182%%238%%182%%168%%185%%164%%215%%247%%181%%231%%209%%185%(V): 6.3; %195%%232%%202%%246%: SMD陶瓷电容-6.3V-10000NF-+/-20%-X5R-0603-BT,TS16949; %208%%161%%192%%224%%195%%251%%179%%198%: SMD陶瓷电容; CODE: 8070649; COMPONENT_HIGH_MAX: 0.9MM; DEVICE: C1608X5R0J106MT0A0E
C73 = C: %182%%238%%182%%168%%185%%164%%215%%247%%181%%231%%209%%185%(V): 10; %195%%232%%202%%246%: SMD陶瓷电容-10V-1000NF-+/-10%-X5R-0402-BT,TS16949; %208%%161%%192%%224%%195%%251%%179%%198%: SMD陶瓷电容; CODE: 8070612; COMPONENT_HIGH_MAX: 0.55MM; DEVICE: CV05X5R105K10AH
C149 C150 C177 = C: %182%%238%%182%%168%%185%%164%%215%%247%%181%%231%%209%%185%(V): 16; %195%%232%%202%%246%: SMD陶瓷电容-16V-100NF-+/-10%-X7R-0402-BT; %208%%161%%192%%224%%195%%251%%179%%198%: SMD陶瓷电容; CODE: 8070614; COMPONENT_HIGH_MAX: 0.6MM; DEVICE: RMEMK105BJ104KV_FR
C263 = C: %182%%238%%182%%168%%185%%164%%215%%247%%181%%231%%209%%185%(V): 50; %195%%232%%202%%246%: SMD陶瓷电容-50V-100NF-±10%-X7R-0603; %208%%161%%192%%224%%195%%251%%179%%198%: SMD陶瓷电容; CODE: 8070627; COMPONENT_HIGH_MAX: 0.9MM; DEVICE: C1608X7R1H104KT000N
C350 C351 C391 = C: %182%%238%%182%%168%%185%%164%%215%%247%%181%%231%%209%%185%(V): 10; %195%%232%%202%%246%: SMD陶瓷电容-10V-2200NF-+/-10%-X5R-0603; %208%%161%%192%%224%%195%%251%%179%%198%: SMD陶瓷电容; CODE: 8070573; COMPONENT_HIGH_MAX: 0.9MM; DEVICE: GRM188R61A225KE34D
D3 = IRM-3638A_0: %195%%232%%202%%246%: 红外遥控接收头-5V-0.001A-0.015KM-38KHZ-940NM-7*8*3.75; %208%%161%%192%%224%%195%%251%%179%%198%: 红外遥控接收头; COMPONENT_HIGH_MAX: 6.95MM; DEVICE: TSOP4838
J21 = MMC10S5: %195%%232%%202%%246%: 板卡座类连接器-MICRO-SD卡座-8PIN-PUSH-PUSH-1.1MM-无锁扣-无-1MM-厚度1.45MM-终端专用; CODE: 14240249; COMPONENT_HIGH_MAX: 1.55MM; DEVICE: 5031820832
LED1 = LED2-3_E: %195%%232%%202%%246%: 发光二极管-0.25CD-红绿625NM/570NM-25MA-插装-共阴-终端专用-00500098; CODE: 15020190; COMPONENT_HIGH_MAX: 7.2MM; DEVICE: 209_3SYGSURC_S530_A3HW
Q1 Q2 Q5 = NPN-BEC: %195%%232%%202%%246%: 三极管-NPN-45V-100MA-225MW-200MV@100MA-SOT-23-180@2MA; %208%%161%%192%%224%%195%%251%%179%%198%: 三极管; CODE: 15050206; COMPONENT_HIGH_MAX: 1.26MM; DEVICE: BC847AE6327
Q15 = FETP-GSD: %195%%232%%202%%246%: MOSFET-P沟道--8V--3A-50MOHM--8V-SOT23; %208%%161%%192%%224%%195%%251%%179%%198%: MOSFET; CODE: 15060134; COMPONENT_HIGH_MAX: 1.11MM; DEVICE: IRLML6401TR
R2 R22 R31 R34 = R: %182%%238%%182%%168%%185%%166%%194%%202%(W): 0.06; %195%%232%%202%%246%: 片式厚膜电阻器-0.0625W-1000OHM-+/-5%-0402-BT; %208%%161%%192%%224%%195%%251%%179%%198%: 片式厚膜电阻器; %215%%232%%214%%181%%212%%202%%208%%237%%198%%171%%178%%238%: +/-5%; CODE: 7090809; COMPONENT_HIGH_MAX: 0.4MM; DEVICE: RC0402JR_071KL
R3 R39 R48 R60 R229 = R: %182%%238%%182%%168%%185%%166%%194%%202%(W): 0.06; %195%%232%%202%%246%: 片式厚膜电阻器-0.0625W-4700OHM-+/-5%-0402-BT; %208%%161%%192%%224%%195%%251%%179%%198%: 片式厚膜电阻器; %215%%232%%214%%181%%212%%202%%208%%237%%198%%171%%178%%238%: +/-5%; CODE: 7090793; COMPONENT_HIGH_MAX: 0.4MM; DEVICE: RK73B1ELTP472J
R76 R77 = R: %182%%238%%182%%168%%185%%166%%194%%202%(W): 0.1; %195%%232%%202%%246%: 片式厚膜电阻器-0.1W-10000OHM-+/-1%-0603; %208%%161%%192%%224%%195%%251%%179%%198%: 片式厚膜电阻器; %215%%232%%214%%181%%212%%202%%208%%237%%198%%171%%178%%238%: +/-1%; CODE: 7090889; COMPONENT_HIGH_MAX: 0.55MM; DEVICE: RC_03K1002FT
R86 = R: %182%%238%%182%%168%%185%%166%%194%%202%(W): 0.1; %195%%232%%202%%246%: 片式厚膜电阻器-0.1W-0OHM-<50MOHM-0603-1A-BT,TS16949; %208%%161%%192%%224%%195%%251%%179%%198%: 片式厚膜电阻器; %215%%232%%214%%181%%212%%202%%208%%237%%198%%171%%178%%238%: <50MOHM; CODE: 7090522; COMPONENT_HIGH_MAX: 0.55MM; DEVICE: RC0603JR_070RL
R140 = R: %182%%238%%182%%168%%185%%166%%194%%202%(W): 0.06; %195%%232%%202%%246%: 片式厚膜电阻器-0.0625W-10000OHM-+/-5%-0402-BT; %208%%161%%192%%224%%195%%251%%179%%198%: 片式厚膜电阻器; %215%%232%%214%%181%%212%%202%%208%%237%%198%%171%%178%%238%: +/-5%; CODE: 7090815; COMPONENT_HIGH_MAX: 0.4MM; DEVICE: RC_02W103JT
R149 = R: %182%%238%%182%%168%%185%%166%%194%%202%(W): 0.1; %195%%232%%202%%246%: 片式厚膜电阻器-0.1W-4700OHM-+/-5%-0603-抗硫化; %208%%161%%192%%224%%195%%251%%179%%198%: 片式厚膜电阻器; %215%%232%%214%%181%%212%%202%%208%%237%%198%%171%%178%%238%: +/-5%; CODE: 7090246; DEVICE: RC0603JR_074K7
R8 R49 R151-R156 = R: %182%%238%%182%%168%%185%%166%%194%%202%(W): 0.06; %195%%232%%202%%246%: 片式厚膜电阻器-0.0625W-47000OHM-+/-5%-0402-ELOM; %208%%161%%192%%224%%195%%251%%179%%198%: 片式厚膜电阻器; %215%%232%%214%%181%%212%%202%%208%%237%%198%%171%%178%%238%: +/-5%; CODE: 7090819; DEVICE: RC0402JR_0747K
R9 R178 = R: %182%%238%%182%%168%%185%%166%%194%%202%(W): 0.06; %195%%232%%202%%246%: 片式厚膜电阻器-0.0625W-75OHM-+/-1%-0402; %208%%161%%192%%224%%195%%251%%179%%198%: 片式厚膜电阻器; %215%%232%%214%%181%%212%%202%%208%%237%%198%%171%%178%%238%: +/-1%; CODE: 7091321; COMPONENT_HIGH_MAX: 0.4MM; DEVICE: RC_02W750FT
R210 = R: %182%%238%%182%%168%%185%%166%%194%%202%(W): 0.1; %195%%232%%202%%246%: 片式厚膜电阻器-0.1W-1000OHM-+/-5%-0603; %208%%161%%192%%224%%195%%251%%179%%198%: 片式厚膜电阻器; %215%%232%%214%%181%%212%%202%%208%%237%%198%%171%%178%%238%: +/-5%; CODE: 7090277; COMPONENT_HIGH_MAX: 0.55MM; DEVICE: RC0603JR_071K
R267 = R: %182%%238%%182%%168%%185%%166%%194%%202%(W): 0.06; %195%%232%%202%%246%: 片式厚膜电阻器-0.1W-100OHM-±5%-0603; %208%%161%%192%%224%%195%%251%%179%%198%: 片式厚膜电阻器; %215%%232%%214%%181%%212%%202%%208%%237%%198%%171%%178%%238%: ±5%; CODE: 7090269; COMPONENT_HIGH_MAX: 0.55MM; DEVICE: RC0603JR_07100RL
C32 C33 = C: %195%%232%%202%%246%: SMD陶瓷电容-6.3V-330NF-+/-10%-X5R-0402-终端专用; %208%%161%%192%%224%%195%%251%%179%%198%: SMD陶瓷电容; CODE: 8070953; COMPONENT_HIGH_MAX: 0.55MM; DEVICE: C1005X5R0J334K
C54 C55 = C: %182%%238%%182%%168%%185%%164%%215%%247%%181%%231%%209%%185%(V): 50; %195%%232%%202%%246%: SMD陶瓷电容-50V-0.047NF-+/-5%-NP0-0402; %208%%161%%192%%224%%195%%251%%179%%198%: SMD陶瓷电容; CODE: 8070549; COMPONENT_HIGH_MAX: 0.55MM; DEVICE: C0402C470J5GAC_7867
C140 C339 = C: %182%%238%%182%%168%%185%%164%%215%%247%%181%%231%%209%%185%(V): 50; %195%%232%%202%%246%: SMD陶瓷电容-50V-1NF-+/-10%-X7R-0402-BT; %208%%161%%192%%224%%195%%251%%179%%198%: SMD陶瓷电容; CODE: 8070531; COMPONENT_HIGH_MAX: 0.55MM; DEVICE: 04025C102KAT2A
C153 C154 C158 = C: %182%%238%%182%%168%%185%%164%%215%%247%%181%%231%%209%%185%(V): 16; %195%%232%%202%%246%: SMD陶瓷电容-16V-100NF-±10%-X7R-0402; %208%%161%%192%%224%%195%%251%%179%%198%: SMD陶瓷电容; CODE: 8070614; COMPONENT_HIGH_MAX: 0.6MM; DEVICE: RMEMK105BJ104KV_FR
C316 C317 = C: %182%%238%%182%%168%%185%%164%%215%%247%%181%%231%%209%%185%(V): 50; %195%%232%%202%%246%: SMD陶瓷电容-50V-0.68NF-+/-5%-NP0-0402-供电专用-供电专用; %208%%161%%192%%224%%195%%251%%179%%198%: SMD陶瓷电容; CODE: 8070853; COMPONENT_HIGH_MAX: 0.55MM; DEVICE: C0402C681J5GAC7867
R19 R20 = R: %182%%238%%182%%168%%185%%166%%194%%202%(W): 0.1; %195%%232%%202%%246%: 片式厚膜电阻器-0.1W-75000OHM-+/-1% -0603; %208%%161%%192%%224%%195%%251%%179%%198%: 片式厚膜电阻器; %215%%232%%214%%181%%212%%202%%208%%237%%198%%171%%178%%238%: +/-1%; CODE: 7091238; COMPONENT_HIGH_MAX: 0.55MM; DEVICE: RK73H1JTTD7502F
R27 R28 = R: %182%%238%%182%%168%%185%%166%%194%%202%(W): 0.1; %195%%232%%202%%246%: 片式厚膜电阻器-0.1W-5100OHM-+/-1%-0603; %208%%161%%192%%224%%195%%251%%179%%198%: 片式厚膜电阻器; %215%%232%%214%%181%%212%%202%%208%%237%%198%%171%%178%%238%: +/-1%; CODE: 7091295; COMPONENT_HIGH_MAX: 0.55MM; DEVICE: RC0603FR_075K1L
R50 R183 = R: %182%%238%%182%%168%%185%%166%%194%%202%(W): 0.06; %195%%232%%202%%246%: 片式厚膜电阻器-0.0625W-470000OHM-±1%-0402; %208%%161%%192%%224%%195%%251%%179%%198%: 片式厚膜电阻器; %215%%232%%214%%181%%212%%202%%208%%237%%198%%171%%178%%238%: ±1%; CODE: 7090855; COMPONENT_HIGH_MAX: 0.4MM; DEVICE: RK73H1ETTP4703F
R57 = R: %182%%238%%182%%168%%185%%166%%194%%202%(W): 0.06; %195%%232%%202%%246%: 片式厚膜电阻器-0.0625W-2200OHM-+/-1%-0402--供电专用-07090810-供电专用; %208%%161%%192%%224%%195%%251%%179%%198%: 片式厚膜电阻器; %215%%232%%214%%181%%212%%202%%208%%237%%198%%171%%178%%238%: +/-1%; CODE: 7091537; COMPONENT_HIGH_MAX: 0.4MM; DEVICE: RC0402FR_072K2L2
R66 = R: %182%%238%%182%%168%%185%%166%%194%%202%(W): 0.06; %195%%232%%202%%246%: 片式厚膜电阻器-0.0625W-470000OHM-+/-1%-0402; %208%%161%%192%%224%%195%%251%%179%%198%: 片式厚膜电阻器; %215%%232%%214%%181%%212%%202%%208%%237%%198%%171%%178%%238%: +/-1%; CODE: 7090855; COMPONENT_HIGH_MAX: 0.4MM; DEVICE: RK73H1ETTP4703F
R72 R74 = R: %195%%232%%202%%246%: 片式厚膜电阻器-0.0625W-560OHM-+/-5%-0402-终端专用-终端专用; %208%%161%%192%%224%%195%%251%%179%%198%: 片式厚膜电阻器; CODE: 7091285; COMPONENT_HIGH_MAX: 0.4MM; DEVICE: RC0402JR_07560RL
R90 = R: %182%%238%%182%%168%%185%%166%%194%%202%(W): 0.06; %195%%232%%202%%246%: 片式厚膜电阻器-0.0625W-1000OHM-±5%-0402; %208%%161%%192%%224%%195%%251%%179%%198%: 片式厚膜电阻器; %215%%232%%214%%181%%212%%202%%208%%237%%198%%171%%178%%238%: ±5%; CODE: 7090809; COMPONENT_HIGH_MAX: 0.4MM; DEVICE: RC0402JR_071KL
R91 = R: %182%%238%%182%%168%%185%%166%%194%%202%(W): 0.06; %195%%232%%202%%246%: 片式厚膜电阻器-0.0625W-5600OHM-+/-1%-0402-BT; %208%%161%%192%%224%%195%%251%%179%%198%: 片式厚膜电阻器; %215%%232%%214%%181%%212%%202%%208%%237%%198%%171%%178%%238%: +/-1%; CODE: 7091275; COMPONENT_HIGH_MAX: 0.4MM; DEVICE: RK73H1ETTP5601F
R145 R146 = R: %182%%238%%182%%168%%185%%166%%194%%202%(W): 0.06; %195%%232%%202%%246%: 片式厚膜电阻器-0.0625W-100000OHM-+/-5%-0402-BT; %208%%161%%192%%224%%195%%251%%179%%198%: 片式厚膜电阻器; %215%%232%%214%%181%%212%%202%%208%%237%%198%%171%%178%%238%: +/-5%; CODE: 7090831; COMPONENT_HIGH_MAX: 0.4MM; DEVICE: RK73B1ELTP104J
R179 = R: %182%%238%%182%%168%%185%%166%%194%%202%(W): 0.1; %195%%232%%202%%246%: 片式厚膜电阻器-0.1W-10OHM-+/-5%-0603-TS16949; %208%%161%%192%%224%%195%%251%%179%%198%: 片式厚膜电阻器; %215%%232%%214%%181%%212%%202%%208%%237%%198%%171%%178%%238%: +/-5%; CODE: 7090264; COMPONENT_HIGH_MAX: 0.55MM; DEVICE: RC0603JR_0710R
R193 R194 = R: %182%%238%%182%%168%%185%%166%%194%%202%(W): 0.06; %195%%232%%202%%246%: 片式厚膜电阻器-0.0625W-20000OHM-+/-1%-0402-TS16949; %208%%161%%192%%224%%195%%251%%179%%198%: 片式厚膜电阻器; %215%%232%%214%%181%%212%%202%%208%%237%%198%%171%%178%%238%: +/-1%; CODE: 7091374; COMPONENT_HIGH_MAX: 0.4MM; DEVICE: RC_02W2002FT
U5 = SGM8903
C23 = C: %182%%238%%182%%168%%185%%164%%215%%247%%181%%231%%209%%185%(V): 2000; %195%%232%%202%%246%: SMD陶瓷电容-2000V-1NF-+/-20%-X7R-1206; %208%%161%%192%%224%%195%%251%%179%%198%: SMD陶瓷电容; CODE: 8070439; COMPONENT_HIGH_MAX: 1.52MM; DEVICE: 1206GC102MAT1A
C297 C307 = C: %182%%238%%182%%168%%185%%164%%215%%247%%181%%231%%209%%185%(V): 16; %195%%232%%202%%246%: SMD陶瓷电容-16V-10NF-+/-10%-X7R-0402-BT,TS16949; %208%%161%%192%%224%%195%%251%%179%%198%: SMD陶瓷电容; CODE: 8070449; COMPONENT_HIGH_MAX: 0.55MM; DEVICE: GRM155R71C103KA01D
J18 = WBC1X41: %195%%232%%202%%246%: 普通插座-4PIN-单排-直式-1.25MM-2MM-THT-1A; %208%%161%%192%%224%%195%%251%%179%%198%: 普通插座; CODE: 14100167; COMPONENT_HIGH_MAX: 4.2MM; DEVICE: SDW12501_4A_HW
J25 = MJ8-L: %195%%232%%202%%246%: 网口连接器-单排-单端口-8PIN-8BIT-非屏蔽-模型插座/侧面插入型-引脚长2.54MM-带固定脚/带灯; %208%%161%%192%%224%%195%%251%%179%%198%: 网口连接器; COMPONENT_HIGH_MAX: 13.2MM; DEVICE: 406533_1
R26 R30 = R: %182%%238%%182%%168%%185%%166%%194%%202%(W): 0.06; %195%%232%%202%%246%: 片式厚膜电阻器-0.0625W-4700OHM-+/-5%-0402; %208%%161%%192%%224%%195%%251%%179%%198%: 片式厚膜电阻器; %215%%232%%214%%181%%212%%202%%208%%237%%198%%171%%178%%238%: +/-5%; CODE: 7090793; COMPONENT_HIGH_MAX: 0.4MM; DEVICE: RK73B1ELTP472J
R59 R62-R64 R67 R79 = R: %182%%238%%182%%168%%185%%166%%194%%202%(W): 0.06; %195%%232%%202%%246%: 片式厚膜电阻器-0.0625W-330OHM-+/-1%-0402-BT; %208%%161%%192%%224%%195%%251%%179%%198%: 片式厚膜电阻器; %215%%232%%214%%181%%212%%202%%208%%237%%198%%171%%178%%238%: +/-1%; CODE: 7091333; COMPONENT_HIGH_MAX: 0.4MM; DEVICE: RC_02W3300FT
R135 R136 = R: %182%%238%%182%%168%%185%%166%%194%%202%(W): 0.06; %195%%232%%202%%246%: 片式厚膜电阻器-0.0625W-10000OHM-±5%-0402; %208%%161%%192%%224%%195%%251%%179%%198%: 片式厚膜电阻器; %215%%232%%214%%181%%212%%202%%208%%237%%198%%171%%178%%238%: ±5%; CODE: 7090815; COMPONENT_HIGH_MAX: 0.4MM; DEVICE: RC_02W103JT
R269-R272 = R: %182%%238%%182%%168%%185%%166%%194%%202%(W): 0.13; %195%%232%%202%%246%: 片式厚膜电阻器-0.125W-75OHM-±1%-0805; %208%%161%%192%%224%%195%%251%%179%%198%: 片式厚膜电阻器; %215%%232%%214%%181%%212%%202%%208%%237%%198%%171%%178%%238%: ±1%; CODE: 7090362; DEVICE: RC0805FR_0775R
T2 = 000-7090-37R: %195%%232%%202%%246%: LAN变压器-1CT:1CT-0.35MH-0UH-1路-2变压器-100BASE-T接口模块-SMT; %208%%161%%192%%224%%195%%251%%179%%198%: LAN变压器; CODE: 9050085; COMPONENT_HIGH_MAX: 6.2MM; DEVICE: H1102T
U8 = CS2203-25_1
C17 C79 = C: %182%%238%%182%%168%%185%%164%%215%%247%%181%%231%%209%%185%(V): 50; %195%%232%%202%%246%: SMD陶瓷电容-50V-0.18NF-+/-5%-NPO-0402; %208%%161%%192%%224%%195%%251%%179%%198%: SMD陶瓷电容; CODE: 8070637; COMPONENT_HIGH_MAX: 0.55MM; DEVICE: CC0402JRNPO9BB181
C80 = C: %182%%238%%182%%168%%185%%164%%215%%247%%181%%231%%209%%185%(V): 50; %195%%232%%202%%246%: SMD陶瓷电容-50V-0.1NF-±5%-NPO-0402; %208%%161%%192%%224%%195%%251%%179%%198%: SMD陶瓷电容; CODE: 8070450; COMPONENT_HIGH_MAX: 0.55MM; DEVICE: 04025A101JAT2A
D9 = D2-3_A: %195%%232%%202%%246%: 开关二极管-70V-200MA-1.25V-6NS-串联-SOT-23-2 FIT; %208%%161%%192%%224%%195%%251%%179%%198%: 开关二极管; CODE: 15010042; COMPONENT_HIGH_MAX: 1.26MM; DEVICE: BAV99B5003
J34 = MIC6M2_M: %195%%232%%202%%246%: 耳机连接器-3.5MM-5PIN-弯式-THT-00486672; CODE: 14240414; COMPONENT_HIGH_MAX: 5MM; DEVICE: 8967_3506ADT_M_A
L6 = L: %195%%232%%202%%246%: 贴片电感器-0.22UH-+/-5%-3.77OHM-0.3A-0402; %208%%161%%192%%224%%195%%251%%179%%198%: 贴片电感器; CODE: 10031264; COMPONENT_HIGH_MAX: 0.55MM; DEVICE: LGHK1005R22J_T
D19 D20 = D_A: %195%%232%%202%%246%: 肖特基二极管-10V-3A-0.24V-SOD323-BT; %208%%161%%192%%224%%195%%251%%179%%198%: 肖特基二极管; CODE: 15010252; COMPONENT_HIGH_MAX: 1.1MM; DEVICE: BAT60BE6327
J26 = WBC1X19S4M2: %195%%232%%202%%246%: IO连接器-HDMI 母座-19PIN-弯式-SMT带DIP脚-终端专用; %208%%161%%192%%224%%195%%251%%179%%198%: IO连接器; CODE: 14240146; COMPONENT_HIGH_MAX: 6.38MM; DEVICE: 1827059_3
R186 R187 = R: %182%%238%%182%%168%%185%%166%%194%%202%(W): 0.06; %195%%232%%202%%246%: 片式厚膜电阻器-0.0625W-2000OHM-+/-1%-0402-BT; %208%%161%%192%%224%%195%%251%%179%%198%: 片式厚膜电阻器; %215%%232%%214%%181%%212%%202%%208%%237%%198%%171%%178%%238%: +/-1%; CODE: 7091354; COMPONENT_HIGH_MAX: 0.4MM; DEVICE: RC_02W2001FT
R268 = R: %182%%238%%182%%168%%185%%166%%194%%202%(W): 0.06; %195%%232%%202%%246%: 片式厚膜电阻器-0.0625W-27000OHM-+/-5%-0402; %208%%161%%192%%224%%195%%251%%179%%198%: 片式厚膜电阻器; %215%%232%%214%%181%%212%%202%%208%%237%%198%%171%%178%%238%: +/-5%; CODE: 7090852; COMPONENT_HIGH_MAX: 0.4MM; DEVICE: RK73B1ETTP273J
U4 = CS0806U
U23 = CS0806S: #: 3
U24 = CS0806S

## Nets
3V3: J18.4 R2.1(A) R3.1(A) R34.1(A) R60.1(A) R135.1(A) R136.1(A) R140.2(B) R178.2(B) ; also on sheet 4 5 6 9
3V3_MOS: C73.1(A) D9.2(K) D19.2(A) J25.10 J25.12 Q15.2(S) R26.1(A) R30.1(A) R77.1(A) R86.1(A) R155.1(A) ; also on sheet 5 6 7 8 9 13 14
3V3_SD: C263.1(A) C391.1(A) J21.4(VDD) Q15.3(D) R86.2(B) R210.1(A)
5V0_MOS: D20.2(A) R179.1(A) ; also on sheet 5 10 14
5V0_MOS_HDMI: C150.1(A) D20.1(K) J26.18 R186.2(B) R187.2(B) U4.5(VDD)
GND: C17.2(B) C23.2(B) C33.1(A) C47.2(B) C79.2(B) C140.2(B) C149.2(B) C150.2(B) C153.2(B) C154.2(B) C158.2(B) C177.2(B) C263.2(B) C297.2(B) C307.2(B) C316.2(B) C317.2(B) C320.2(B) C339.2(B) C363.2(B) C391.2(B) D3.2(GND) D9.1(A) J18.1 J21.6(VSS) J21.10(DETECT_TERM) J21.11(S1) J21.12(S2) J21.13(S3) J21.14(S4) J21.15(S5) J26.2 J26.5 J26.8 J26.11 J26.17 J26.20(S1) J26.21(S2) J26.22(S3) J26.23(S4) J34.5(P5) LED1.2(C) Q1.2(E) Q2.2(E) Q5.2(E) R8.1(A) R9.2(B) R39.2(B) R48.2(B) R50.2(B) R57.2(B) R145.2(B) R146.2(B) R149.2(B) R183.2(B) R210.2(B) R229.2(B) U4.2(GND) U5.1(+INR) U5.4(SGND) U5.10(PGND) U5.14(+INL) U23.3(GND1) U23.8(GND2) U24.3(GND1) U24.8(GND2) ; also on sheet 3 4 5 6 7 8 9 10 11 12 13 14
VDD_AUDIO: C158.1(A) C320.1(A) R66.2(B) R91.1(A) R179.2(B) U5.9(PVDD)
ADAC_VOUTL: C350.2(B) R50.1(A) ; also on sheet 7
ADAC_VOUTR: C351.1(A) R183.1(A) ; also on sheet 7
AUDIO_L: C339.1(A) J34.3(P3) R72.2(B)
AUDIO_R: C140.1(A) J34.2(P2) R74.1(A)
CVBS: C79.1(A) C80.1(A) L6.1(A) R9.1(A) ; also on sheet 7
CVBS_OUT: C17.1(A) C80.2(B) D9.3(COM) J34.4(P4) L6.2(B)
HDMI_TX0N: J26.9 U24.2(IO2_IN) U24.9(IO2_OUT) ; also on sheet 7
HDMI_TX0P: J26.7 U24.1(IO1_IN) U24.10(IO1_OUT) ; also on sheet 7
HDMI_TX1N: J26.6 U23.5(IO4_IN) U23.6(IO4_OUT) ; also on sheet 7
HDMI_TX1P: J26.4 U23.4(IO3_IN) U23.7(IO3_OUT) ; also on sheet 7
HDMI_TX2N: J26.3 U23.2(IO2_IN) U23.9(IO2_OUT) ; also on sheet 7
HDMI_TX2P: J26.1 U23.1(IO1_IN) U23.10(IO1_OUT) ; also on sheet 7
HDMI_TX_CEC: J26.13 R268.2(B) U4.3(I/O2) ; also on sheet 7
HDMI_TX_HOTPLUG: C149.1(A) J26.19 R8.2(B) U4.4(I/O3) ; also on sheet 7
HDMI_TX_SCL: J26.15 R186.1(A) U4.1(I/O1) ; also on sheet 7
HDMI_TX_SDA: J26.16 R187.1(A) U4.6(I/O4) ; also on sheet 7
HDMI_TXCN: J26.12 U24.5(IO4_IN) U24.6(IO4_OUT) ; also on sheet 7
HDMI_TXCP: J26.10 U24.4(IO3_IN) U24.7(IO3_OUT) ; also on sheet 7
IR_IN: D3.1(OUT) R140.1(A) ; also on sheet 6
LED0_BASE: R26.2(B) R67.2(B) ; also on sheet 6
LED0_LINK_ACT: R30.2(B) R79.2(B) ; also on sheet 6
LED_GREEN: R3.2(B) R22.1(A) R48.1(A) ; also on sheet 6
LED_RED: R31.1(A) R39.1(A) R60.2(B) ; also on sheet 6
MUTE_CTRL: R90.1(A) ; also on sheet 7
RX+_PHY0: R63.1(A) U8.3(IO2_P1) U8.6(IO2_P2) ; also on sheet 6
RX-_PHY0: R64.1(A) U8.4(IO2_N1) U8.5(IO2_N2) ; also on sheet 6
SDIO0_CARD_DETECT: J21.9(SWITCH_TERM) R155.2(B) ; also on sheet 6
SDIO0_CCLK_OUT: J21.5(CLK) ; also on sheet 6
SDIO0_CCMD: J21.3(CMD) R153.2(B) ; also on sheet 6
SDIO0_CDATA0: J21.7(DAT0) R152.2(B) ; also on sheet 6
SDIO0_CDATA1: J21.8(DAT1) R151.2(B) ; also on sheet 6
SDIO0_CDATA2: J21.1(DATA2) R156.2(B) ; also on sheet 6
SDIO0_CDATA3: J21.2(CD/DAT3) R154.2(B) ; also on sheet 6
SDIO0_PWREN: R76.1(A) R149.1(A) ; also on sheet 6
SDIO_3318: R151.1(A) R152.1(A) R153.1(A) R154.1(A) R156.1(A) ; also on sheet 6
TX+_PHY0: R59.1(A) U8.1(IO1_P1) U8.8(IO1_P2) ; also on sheet 6
TX-_PHY0: R62.1(A) U8.2(IO1_N1) U8.7(IO1_N2) ; also on sheet 6
UART0_RXD: J18.2 R136.2(B) ; also on sheet 7
UART0_TXD: J18.3 R135.2(B) ; also on sheet 7
N00501: D19.1(K) R268.1(A)
N01184: C153.1(A) C307.1(A) T2.2(CTD)
N01194: J25.4 J25.5 R272.2(B)
N01204: J25.2 T2.14(TX-)
N01212: J25.1 T2.16(TX+)
N01220: C23.1(A) R269.1(A) R270.1(A) R271.1(A) R272.1(A)
N01240: J25.3 T2.11(RX+)
N01248: J25.6 T2.9(RX-)
N01252: R269.2(B) T2.10(CRX)
N01258: R271.2(B) T2.15(CTX)
N01264: J25.7 J25.8 R270.2(B)
N01274: J25.11 R79.1(A)
N01278: J25.9 R67.1(A)
N01282: C154.1(A) C297.1(A) T2.7(CRD)
N01881: R49.2(B) R57.1(A) R91.2(B)
N01893: C54.1(A) R20.1(A) R72.1(A) R145.1(A) U5.12(OUTL)
N01945: C32.2(B) U5.8(CP)
N01953: C32.1(A) U5.7(CN)
N01961: C33.2(B) U5.6(PVSS)
N01965: C363.1(A) R66.1(A) R90.2(B) R229.1(A) U5.5(EN)
N01987: C55.2(B) R19.2(B) R74.2(B) R146.1(A) U5.3(OUTR)
N02013: C317.1(A) R19.1(A) R27.1(A) R193.2(B)
N02033: C55.1(A) R27.2(B) U5.2(-INR)
N02043: C351.2(B) R193.1(A)
N02063: C54.2(B) R28.1(A) U5.13(-INL)
N02073: C316.1(A) R20.2(B) R28.2(B) R194.1(A)
N02085: C350.1(A) R194.2(B)
N02089: R49.1(A) U5.11(UVP)
N02814: C73.2(B) Q15.1(G) R77.2(B) R267.1(A)
N02844: Q5.3(C) R267.2(B)
N02848: Q5.1(B) R76.2(B)
N02874: C47.1(A) C177.1(A) D3.3(VCC) R178.1(A)
N02960: Q1.1(B) R22.2(B)
N02964: Q2.1(B) R31.2(B)
N02968: LED1.3(A2) Q1.3(C) R2.2(B)
N02980: LED1.1(A1) Q2.3(C) R34.2(B)
N16846302: R59.2(B) T2.1(TD+)
N16846304: R62.2(B) T2.3(TD-)
N16846306: R63.2(B) T2.6(RD+)
N16846308: R64.2(B) T2.8(RD-)

Not connected (* = marked no-connect by the designer): J25 13(M1)* 14(M2)*; J26 14* 24(M1)* 25(M2)*; J34 6(NC)* 7(M1)* 8(M2)*

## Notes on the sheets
sheet 15
- SD CARD/IR
- LED
- IR
- R ON+G OFF->STBY
- R OFF+G ON->WORK
- R OFF+G OFF->NO POWER
sheet 16
- Audio Output
- 1%
- 1%
- 1%
- 1%
- 1%
- MUTE_CTL
- 0
- Mute
- 1
- Work
sheet 17
- FE PHY/UART
- Put C153 and C154 close to T2
- UART
sheet 18
- VDAC OUTPUT
- ** Design guideline **
- 1.All channel traces should be separated from other traces by GND.
- 2.ESD components are suggested for ports protection, default BAV99.
sheet 19
- HDMI TX
- ** HDMI Design guideline **
- A.routing
- 1.Route as 100 Ohm differential impedance.
- 2.Differential pairs should be routed on TOP layer only.
- 3.Differential pairs should be separated from other traces by GND .
- B.trace length
- 1.The length for the differential pairs should be less than 5 inches.
- 2.Match trace length of differential pairs, 5 mils max within a pair.
- C.component selection
- 1.REXT resistor should be 6.6K Ohm +/-1%.
- 2.ESD components are suggested for ports protection.
- 3.All equivalent capacitance of ESD components should be < 0.8pF.
